VERSION 5.7 ;
  NOWIREEXTENSIONATPIN ON ;
  DIVIDERCHAR "/" ;
  BUSBITCHARS "[]" ;
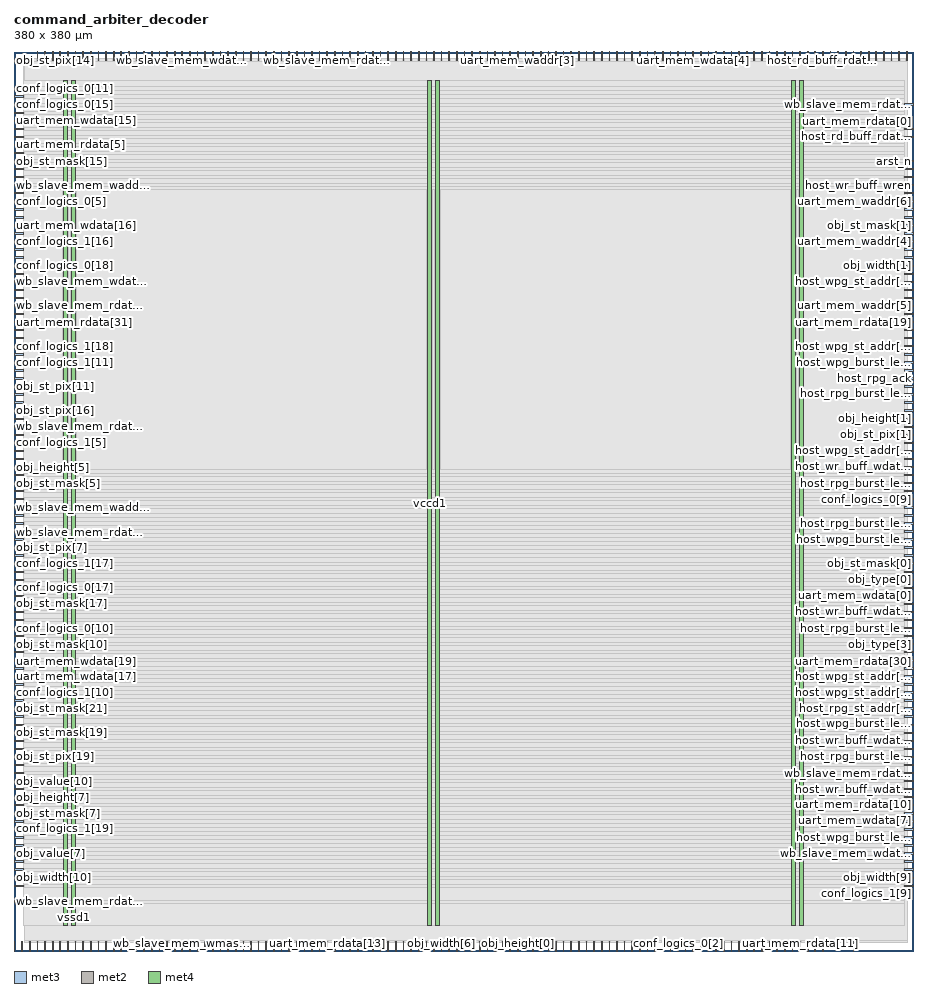
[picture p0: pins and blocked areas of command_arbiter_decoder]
MACRO command_arbiter_decoder
  CLASS BLOCK ;
  FOREIGN command_arbiter_decoder ;
  ORIGIN 0.000 0.000 ;
  SIZE 380.000 BY 380.000 ;
  PIN arst_n
    DIRECTION INPUT ;
    USE SIGNAL ;
    ANTENNAGATEAREA 1.286700 ;
    ANTENNADIFFAREA 0.434700 ;
    PORT
      LAYER met3 ;
        RECT 376.000 333.240 380.000 333.840 ;
    END
  END arst_n
  PIN clk
    DIRECTION INPUT ;
    USE SIGNAL ;
    ANTENNAGATEAREA 1.286700 ;
    ANTENNADIFFAREA 0.434700 ;
    PORT
      LAYER met3 ;
        RECT 0.000 27.240 4.000 27.840 ;
    END
  END clk
  PIN conf_logics_0[0]
    DIRECTION OUTPUT ;
    USE SIGNAL ;
    ANTENNADIFFAREA 0.340600 ;
    PORT
      LAYER met2 ;
        RECT 103.130 0.000 103.410 4.000 ;
    END
  END conf_logics_0[0]
  PIN conf_logics_0[10]
    DIRECTION OUTPUT ;
    USE SIGNAL ;
    ANTENNADIFFAREA 0.340600 ;
    PORT
      LAYER met3 ;
        RECT 0.000 136.040 4.000 136.640 ;
    END
  END conf_logics_0[10]
  PIN conf_logics_0[11]
    DIRECTION OUTPUT ;
    USE SIGNAL ;
    ANTENNADIFFAREA 0.340600 ;
    PORT
      LAYER met3 ;
        RECT 0.000 363.840 4.000 364.440 ;
    END
  END conf_logics_0[11]
  PIN conf_logics_0[12]
    DIRECTION OUTPUT ;
    USE SIGNAL ;
    ANTENNADIFFAREA 0.340600 ;
    PORT
      LAYER met2 ;
        RECT 9.750 376.000 10.030 380.000 ;
    END
  END conf_logics_0[12]
  PIN conf_logics_0[13]
    DIRECTION OUTPUT ;
    USE SIGNAL ;
    ANTENNADIFFAREA 0.340600 ;
    PORT
      LAYER met2 ;
        RECT 83.810 376.000 84.090 380.000 ;
    END
  END conf_logics_0[13]
  PIN conf_logics_0[14]
    DIRECTION OUTPUT ;
    USE SIGNAL ;
    ANTENNADIFFAREA 0.340600 ;
    PORT
      LAYER met2 ;
        RECT 164.310 376.000 164.590 380.000 ;
    END
  END conf_logics_0[14]
  PIN conf_logics_0[15]
    DIRECTION OUTPUT ;
    USE SIGNAL ;
    ANTENNADIFFAREA 0.340600 ;
    PORT
      LAYER met3 ;
        RECT 0.000 357.040 4.000 357.640 ;
    END
  END conf_logics_0[15]
  PIN conf_logics_0[16]
    DIRECTION OUTPUT ;
    USE SIGNAL ;
    ANTENNADIFFAREA 0.340600 ;
    PORT
      LAYER met3 ;
        RECT 0.000 309.440 4.000 310.040 ;
    END
  END conf_logics_0[16]
  PIN conf_logics_0[17]
    DIRECTION OUTPUT ;
    USE SIGNAL ;
    ANTENNADIFFAREA 0.340600 ;
    PORT
      LAYER met3 ;
        RECT 0.000 153.040 4.000 153.640 ;
    END
  END conf_logics_0[17]
  PIN conf_logics_0[18]
    DIRECTION OUTPUT ;
    USE SIGNAL ;
    ANTENNADIFFAREA 0.340600 ;
    PORT
      LAYER met3 ;
        RECT 0.000 289.040 4.000 289.640 ;
    END
  END conf_logics_0[18]
  PIN conf_logics_0[19]
    DIRECTION OUTPUT ;
    USE SIGNAL ;
    ANTENNADIFFAREA 0.340600 ;
    PORT
      LAYER met3 ;
        RECT 0.000 61.240 4.000 61.840 ;
    END
  END conf_logics_0[19]
  PIN conf_logics_0[1]
    DIRECTION OUTPUT ;
    USE SIGNAL ;
    ANTENNADIFFAREA 0.340600 ;
    PORT
      LAYER met2 ;
        RECT 186.850 376.000 187.130 380.000 ;
    END
  END conf_logics_0[1]
  PIN conf_logics_0[20]
    DIRECTION OUTPUT ;
    USE SIGNAL ;
    ANTENNADIFFAREA 0.340600 ;
    PORT
      LAYER met2 ;
        RECT 106.350 0.000 106.630 4.000 ;
    END
  END conf_logics_0[20]
  PIN conf_logics_0[2]
    DIRECTION OUTPUT ;
    USE SIGNAL ;
    ANTENNADIFFAREA 0.340600 ;
    PORT
      LAYER met2 ;
        RECT 280.230 0.000 280.510 4.000 ;
    END
  END conf_logics_0[2]
  PIN conf_logics_0[3]
    DIRECTION OUTPUT ;
    USE SIGNAL ;
    ANTENNADIFFAREA 0.340600 ;
    PORT
      LAYER met2 ;
        RECT 193.290 0.000 193.570 4.000 ;
    END
  END conf_logics_0[3]
  PIN conf_logics_0[4]
    DIRECTION OUTPUT ;
    USE SIGNAL ;
    ANTENNADIFFAREA 0.340600 ;
    PORT
      LAYER met2 ;
        RECT 199.730 376.000 200.010 380.000 ;
    END
  END conf_logics_0[4]
  PIN conf_logics_0[5]
    DIRECTION OUTPUT ;
    USE SIGNAL ;
    ANTENNADIFFAREA 0.340600 ;
    PORT
      LAYER met3 ;
        RECT 0.000 316.240 4.000 316.840 ;
    END
  END conf_logics_0[5]
  PIN conf_logics_0[6]
    DIRECTION OUTPUT ;
    USE SIGNAL ;
    ANTENNADIFFAREA 0.340600 ;
    PORT
      LAYER met2 ;
        RECT 170.750 0.000 171.030 4.000 ;
    END
  END conf_logics_0[6]
  PIN conf_logics_0[7]
    DIRECTION OUTPUT ;
    USE SIGNAL ;
    ANTENNADIFFAREA 0.340600 ;
    PORT
      LAYER met3 ;
        RECT 0.000 132.640 4.000 133.240 ;
    END
  END conf_logics_0[7]
  PIN conf_logics_0[8]
    DIRECTION OUTPUT ;
    USE SIGNAL ;
    ANTENNADIFFAREA 0.340600 ;
    PORT
      LAYER met2 ;
        RECT 116.010 0.000 116.290 4.000 ;
    END
  END conf_logics_0[8]
  PIN conf_logics_0[9]
    DIRECTION OUTPUT ;
    USE SIGNAL ;
    ANTENNADIFFAREA 0.340600 ;
    PORT
      LAYER met3 ;
        RECT 376.000 190.440 380.000 191.040 ;
    END
  END conf_logics_0[9]
  PIN conf_logics_1[0]
    DIRECTION OUTPUT ;
    USE SIGNAL ;
    ANTENNADIFFAREA 0.340600 ;
    PORT
      LAYER met2 ;
        RECT 177.190 0.000 177.470 4.000 ;
    END
  END conf_logics_1[0]
  PIN conf_logics_1[10]
    DIRECTION OUTPUT ;
    USE SIGNAL ;
    ANTENNADIFFAREA 0.340600 ;
    PORT
      LAYER met3 ;
        RECT 0.000 108.840 4.000 109.440 ;
    END
  END conf_logics_1[10]
  PIN conf_logics_1[11]
    DIRECTION OUTPUT ;
    USE SIGNAL ;
    ANTENNADIFFAREA 0.340600 ;
    PORT
      LAYER met3 ;
        RECT 0.000 248.240 4.000 248.840 ;
    END
  END conf_logics_1[11]
  PIN conf_logics_1[12]
    DIRECTION OUTPUT ;
    USE SIGNAL ;
    ANTENNADIFFAREA 0.340600 ;
    PORT
      LAYER met2 ;
        RECT 99.910 376.000 100.190 380.000 ;
    END
  END conf_logics_1[12]
  PIN conf_logics_1[13]
    DIRECTION OUTPUT ;
    USE SIGNAL ;
    ANTENNADIFFAREA 0.340600 ;
    PORT
      LAYER met3 ;
        RECT 0.000 258.440 4.000 259.040 ;
    END
  END conf_logics_1[13]
  PIN conf_logics_1[14]
    DIRECTION OUTPUT ;
    USE SIGNAL ;
    ANTENNADIFFAREA 0.340600 ;
    PORT
      LAYER met2 ;
        RECT 161.090 376.000 161.370 380.000 ;
    END
  END conf_logics_1[14]
  PIN conf_logics_1[15]
    DIRECTION OUTPUT ;
    USE SIGNAL ;
    ANTENNADIFFAREA 0.340600 ;
    PORT
      LAYER met3 ;
        RECT 0.000 329.840 4.000 330.440 ;
    END
  END conf_logics_1[15]
  PIN conf_logics_1[16]
    DIRECTION OUTPUT ;
    USE SIGNAL ;
    ANTENNADIFFAREA 0.340600 ;
    PORT
      LAYER met3 ;
        RECT 0.000 299.240 4.000 299.840 ;
    END
  END conf_logics_1[16]
  PIN conf_logics_1[17]
    DIRECTION OUTPUT ;
    USE SIGNAL ;
    ANTENNADIFFAREA 0.340600 ;
    PORT
      LAYER met3 ;
        RECT 0.000 163.240 4.000 163.840 ;
    END
  END conf_logics_1[17]
  PIN conf_logics_1[18]
    DIRECTION OUTPUT ;
    USE SIGNAL ;
    ANTENNADIFFAREA 0.340600 ;
    PORT
      LAYER met3 ;
        RECT 0.000 255.040 4.000 255.640 ;
    END
  END conf_logics_1[18]
  PIN conf_logics_1[19]
    DIRECTION OUTPUT ;
    USE SIGNAL ;
    ANTENNADIFFAREA 0.340600 ;
    PORT
      LAYER met3 ;
        RECT 0.000 54.440 4.000 55.040 ;
    END
  END conf_logics_1[19]
  PIN conf_logics_1[1]
    DIRECTION OUTPUT ;
    USE SIGNAL ;
    ANTENNADIFFAREA 0.340600 ;
    PORT
      LAYER met3 ;
        RECT 376.000 268.640 380.000 269.240 ;
    END
  END conf_logics_1[1]
  PIN conf_logics_1[20]
    DIRECTION OUTPUT ;
    USE SIGNAL ;
    ANTENNADIFFAREA 0.340600 ;
    PORT
      LAYER met3 ;
        RECT 0.000 47.640 4.000 48.240 ;
    END
  END conf_logics_1[20]
  PIN conf_logics_1[2]
    DIRECTION OUTPUT ;
    USE SIGNAL ;
    ANTENNADIFFAREA 0.340600 ;
    PORT
      LAYER met2 ;
        RECT 215.830 0.000 216.110 4.000 ;
    END
  END conf_logics_1[2]
  PIN conf_logics_1[3]
    DIRECTION OUTPUT ;
    USE SIGNAL ;
    ANTENNADIFFAREA 0.340600 ;
    PORT
      LAYER met2 ;
        RECT 199.730 0.000 200.010 4.000 ;
    END
  END conf_logics_1[3]
  PIN conf_logics_1[4]
    DIRECTION OUTPUT ;
    USE SIGNAL ;
    ANTENNADIFFAREA 0.340600 ;
    PORT
      LAYER met2 ;
        RECT 206.170 376.000 206.450 380.000 ;
    END
  END conf_logics_1[4]
  PIN conf_logics_1[5]
    DIRECTION OUTPUT ;
    USE SIGNAL ;
    ANTENNADIFFAREA 0.340600 ;
    PORT
      LAYER met3 ;
        RECT 0.000 214.240 4.000 214.840 ;
    END
  END conf_logics_1[5]
  PIN conf_logics_1[6]
    DIRECTION OUTPUT ;
    USE SIGNAL ;
    ANTENNADIFFAREA 0.340600 ;
    PORT
      LAYER met2 ;
        RECT 173.970 0.000 174.250 4.000 ;
    END
  END conf_logics_1[6]
  PIN conf_logics_1[7]
    DIRECTION OUTPUT ;
    USE SIGNAL ;
    ANTENNADIFFAREA 0.340600 ;
    PORT
      LAYER met3 ;
        RECT 0.000 166.640 4.000 167.240 ;
    END
  END conf_logics_1[7]
  PIN conf_logics_1[8]
    DIRECTION OUTPUT ;
    USE SIGNAL ;
    ANTENNADIFFAREA 0.340600 ;
    PORT
      LAYER met2 ;
        RECT 122.450 0.000 122.730 4.000 ;
    END
  END conf_logics_1[8]
  PIN conf_logics_1[9]
    DIRECTION OUTPUT ;
    USE SIGNAL ;
    ANTENNADIFFAREA 0.340600 ;
    PORT
      LAYER met3 ;
        RECT 376.000 27.240 380.000 27.840 ;
    END
  END conf_logics_1[9]
  PIN drw_inc_busy
    DIRECTION INPUT ;
    USE SIGNAL ;
    ANTENNAGATEAREA 0.631200 ;
    ANTENNADIFFAREA 0.434700 ;
    PORT
      LAYER met2 ;
        RECT 370.390 376.000 370.670 380.000 ;
    END
  END drw_inc_busy
  PIN drw_inc_start
    DIRECTION OUTPUT ;
    USE SIGNAL ;
    ANTENNADIFFAREA 0.340600 ;
    PORT
      LAYER met2 ;
        RECT 215.830 376.000 216.110 380.000 ;
    END
  END drw_inc_start
  PIN host_rd_buff_empty
    DIRECTION INPUT ;
    USE SIGNAL ;
    PORT
      LAYER met2 ;
        RECT 87.030 0.000 87.310 4.000 ;
    END
  END host_rd_buff_empty
  PIN host_rd_buff_rdata[0]
    DIRECTION INPUT ;
    USE SIGNAL ;
    ANTENNAGATEAREA 0.631200 ;
    ANTENNADIFFAREA 0.434700 ;
    PORT
      LAYER met3 ;
        RECT 376.000 343.440 380.000 344.040 ;
    END
  END host_rd_buff_rdata[0]
  PIN host_rd_buff_rdata[1]
    DIRECTION INPUT ;
    USE SIGNAL ;
    ANTENNAGATEAREA 0.631200 ;
    ANTENNADIFFAREA 0.434700 ;
    PORT
      LAYER met3 ;
        RECT 376.000 312.840 380.000 313.440 ;
    END
  END host_rd_buff_rdata[1]
  PIN host_rd_buff_rdata[2]
    DIRECTION INPUT ;
    USE SIGNAL ;
    ANTENNAGATEAREA 0.631200 ;
    ANTENNADIFFAREA 0.434700 ;
    PORT
      LAYER met2 ;
        RECT 90.250 376.000 90.530 380.000 ;
    END
  END host_rd_buff_rdata[2]
  PIN host_rd_buff_rdata[3]
    DIRECTION INPUT ;
    USE SIGNAL ;
    ANTENNAGATEAREA 0.631200 ;
    ANTENNADIFFAREA 0.434700 ;
    PORT
      LAYER met3 ;
        RECT 376.000 234.640 380.000 235.240 ;
    END
  END host_rd_buff_rdata[3]
  PIN host_rd_buff_rdata[4]
    DIRECTION INPUT ;
    USE SIGNAL ;
    ANTENNAGATEAREA 0.631200 ;
    ANTENNADIFFAREA 0.434700 ;
    PORT
      LAYER met2 ;
        RECT 341.410 376.000 341.690 380.000 ;
    END
  END host_rd_buff_rdata[4]
  PIN host_rd_buff_rdata[5]
    DIRECTION INPUT ;
    USE SIGNAL ;
    ANTENNAGATEAREA 0.631200 ;
    ANTENNADIFFAREA 0.434700 ;
    PORT
      LAYER met3 ;
        RECT 0.000 346.840 4.000 347.440 ;
    END
  END host_rd_buff_rdata[5]
  PIN host_rd_buff_rdata[6]
    DIRECTION INPUT ;
    USE SIGNAL ;
    ANTENNAGATEAREA 0.631200 ;
    ANTENNADIFFAREA 0.434700 ;
    PORT
      LAYER met2 ;
        RECT 305.990 376.000 306.270 380.000 ;
    END
  END host_rd_buff_rdata[6]
  PIN host_rd_buff_rdata[7]
    DIRECTION INPUT ;
    USE SIGNAL ;
    ANTENNAGATEAREA 0.631200 ;
    ANTENNADIFFAREA 0.434700 ;
    PORT
      LAYER met2 ;
        RECT 338.190 376.000 338.470 380.000 ;
    END
  END host_rd_buff_rdata[7]
  PIN host_rd_buff_rden
    DIRECTION OUTPUT ;
    USE SIGNAL ;
    ANTENNADIFFAREA 0.340600 ;
    PORT
      LAYER met3 ;
        RECT 376.000 37.440 380.000 38.040 ;
    END
  END host_rd_buff_rden
  PIN host_rpg_ack
    DIRECTION INPUT ;
    USE SIGNAL ;
    ANTENNAGATEAREA 0.631200 ;
    ANTENNADIFFAREA 0.434700 ;
    PORT
      LAYER met3 ;
        RECT 376.000 241.440 380.000 242.040 ;
    END
  END host_rpg_ack
  PIN host_rpg_burst_length[0]
    DIRECTION OUTPUT ;
    USE SIGNAL ;
    ANTENNADIFFAREA 0.340600 ;
    PORT
      LAYER met3 ;
        RECT 376.000 54.440 380.000 55.040 ;
    END
  END host_rpg_burst_length[0]
  PIN host_rpg_burst_length[1]
    DIRECTION OUTPUT ;
    USE SIGNAL ;
    ANTENNADIFFAREA 0.340600 ;
    PORT
      LAYER met3 ;
        RECT 376.000 319.640 380.000 320.240 ;
    END
  END host_rpg_burst_length[1]
  PIN host_rpg_burst_length[2]
    DIRECTION OUTPUT ;
    USE SIGNAL ;
    ANTENNADIFFAREA 0.340600 ;
    PORT
      LAYER met3 ;
        RECT 376.000 81.640 380.000 82.240 ;
    END
  END host_rpg_burst_length[2]
  PIN host_rpg_burst_length[3]
    DIRECTION OUTPUT ;
    USE SIGNAL ;
    ANTENNADIFFAREA 0.340600 ;
    PORT
      LAYER met3 ;
        RECT 376.000 132.640 380.000 133.240 ;
    END
  END host_rpg_burst_length[3]
  PIN host_rpg_burst_length[4]
    DIRECTION OUTPUT ;
    USE SIGNAL ;
    ANTENNADIFFAREA 0.340600 ;
    PORT
      LAYER met3 ;
        RECT 376.000 258.440 380.000 259.040 ;
    END
  END host_rpg_burst_length[4]
  PIN host_rpg_burst_length[5]
    DIRECTION OUTPUT ;
    USE SIGNAL ;
    ANTENNADIFFAREA 0.340600 ;
    PORT
      LAYER met3 ;
        RECT 376.000 238.040 380.000 238.640 ;
    END
  END host_rpg_burst_length[5]
  PIN host_rpg_burst_length[6]
    DIRECTION OUTPUT ;
    USE SIGNAL ;
    ANTENNADIFFAREA 0.340600 ;
    PORT
      LAYER met3 ;
        RECT 376.000 88.440 380.000 89.040 ;
    END
  END host_rpg_burst_length[6]
  PIN host_rpg_burst_length[7]
    DIRECTION OUTPUT ;
    USE SIGNAL ;
    ANTENNADIFFAREA 0.340600 ;
    PORT
      LAYER met3 ;
        RECT 376.000 180.240 380.000 180.840 ;
    END
  END host_rpg_burst_length[7]
  PIN host_rpg_burst_length[8]
    DIRECTION OUTPUT ;
    USE SIGNAL ;
    ANTENNADIFFAREA 0.340600 ;
    PORT
      LAYER met3 ;
        RECT 376.000 136.040 380.000 136.640 ;
    END
  END host_rpg_burst_length[8]
  PIN host_rpg_burst_length[9]
    DIRECTION OUTPUT ;
    USE SIGNAL ;
    ANTENNADIFFAREA 0.340600 ;
    PORT
      LAYER met3 ;
        RECT 376.000 193.840 380.000 194.440 ;
    END
  END host_rpg_burst_length[9]
  PIN host_rpg_busy
    DIRECTION OUTPUT ;
    USE SIGNAL ;
    ANTENNADIFFAREA 0.340600 ;
    PORT
      LAYER met3 ;
        RECT 376.000 278.840 380.000 279.440 ;
    END
  END host_rpg_busy
  PIN host_rpg_st_addr[0]
    DIRECTION OUTPUT ;
    USE SIGNAL ;
    ANTENNADIFFAREA 0.340600 ;
    PORT
      LAYER met3 ;
        RECT 376.000 78.240 380.000 78.840 ;
    END
  END host_rpg_st_addr[0]
  PIN host_rpg_st_addr[1]
    DIRECTION OUTPUT ;
    USE SIGNAL ;
    ANTENNADIFFAREA 0.340600 ;
    PORT
      LAYER met3 ;
        RECT 376.000 217.640 380.000 218.240 ;
    END
  END host_rpg_st_addr[1]
  PIN host_rpg_st_addr[2]
    DIRECTION OUTPUT ;
    USE SIGNAL ;
    ANTENNADIFFAREA 0.340600 ;
    PORT
      LAYER met3 ;
        RECT 376.000 95.240 380.000 95.840 ;
    END
  END host_rpg_st_addr[2]
  PIN host_rpg_st_addr[3]
    DIRECTION OUTPUT ;
    USE SIGNAL ;
    ANTENNADIFFAREA 0.340600 ;
    PORT
      LAYER met3 ;
        RECT 376.000 102.040 380.000 102.640 ;
    END
  END host_rpg_st_addr[3]
  PIN host_rpg_st_addr[4]
    DIRECTION OUTPUT ;
    USE SIGNAL ;
    ANTENNADIFFAREA 0.340600 ;
    PORT
      LAYER met3 ;
        RECT 376.000 295.840 380.000 296.440 ;
    END
  END host_rpg_st_addr[4]
  PIN host_rpg_st_addr[5]
    DIRECTION OUTPUT ;
    USE SIGNAL ;
    ANTENNADIFFAREA 0.340600 ;
    PORT
      LAYER met3 ;
        RECT 376.000 261.840 380.000 262.440 ;
    END
  END host_rpg_st_addr[5]
  PIN host_rpg_st_addr[6]
    DIRECTION OUTPUT ;
    USE SIGNAL ;
    ANTENNADIFFAREA 0.340600 ;
    PORT
      LAYER met2 ;
        RECT 277.010 0.000 277.290 4.000 ;
    END
  END host_rpg_st_addr[6]
  PIN host_rpg_st_addr[7]
    DIRECTION OUTPUT ;
    USE SIGNAL ;
    ANTENNADIFFAREA 0.340600 ;
    PORT
      LAYER met3 ;
        RECT 376.000 61.240 380.000 61.840 ;
    END
  END host_rpg_st_addr[7]
  PIN host_rpg_st_addr[8]
    DIRECTION OUTPUT ;
    USE SIGNAL ;
    ANTENNADIFFAREA 0.340600 ;
    PORT
      LAYER met2 ;
        RECT 257.690 0.000 257.970 4.000 ;
    END
  END host_rpg_st_addr[8]
  PIN host_rpg_st_addr[9]
    DIRECTION OUTPUT ;
    USE SIGNAL ;
    ANTENNADIFFAREA 0.340600 ;
    PORT
      LAYER met3 ;
        RECT 376.000 166.640 380.000 167.240 ;
    END
  END host_rpg_st_addr[9]
  PIN host_wpg_ack
    DIRECTION INPUT ;
    USE SIGNAL ;
    ANTENNAGATEAREA 0.631200 ;
    ANTENNADIFFAREA 0.434700 ;
    PORT
      LAYER met2 ;
        RECT 222.270 376.000 222.550 380.000 ;
    END
  END host_wpg_ack
  PIN host_wpg_burst_length[0]
    DIRECTION OUTPUT ;
    USE SIGNAL ;
    ANTENNADIFFAREA 0.340600 ;
    PORT
      LAYER met3 ;
        RECT 376.000 47.640 380.000 48.240 ;
    END
  END host_wpg_burst_length[0]
  PIN host_wpg_burst_length[1]
    DIRECTION OUTPUT ;
    USE SIGNAL ;
    ANTENNADIFFAREA 0.340600 ;
    PORT
      LAYER met3 ;
        RECT 376.000 302.640 380.000 303.240 ;
    END
  END host_wpg_burst_length[1]
  PIN host_wpg_burst_length[2]
    DIRECTION OUTPUT ;
    USE SIGNAL ;
    ANTENNADIFFAREA 0.340600 ;
    PORT
      LAYER met3 ;
        RECT 376.000 98.640 380.000 99.240 ;
    END
  END host_wpg_burst_length[2]
  PIN host_wpg_burst_length[3]
    DIRECTION OUTPUT ;
    USE SIGNAL ;
    ANTENNADIFFAREA 0.340600 ;
    PORT
      LAYER met3 ;
        RECT 376.000 105.440 380.000 106.040 ;
    END
  END host_wpg_burst_length[3]
  PIN host_wpg_burst_length[4]
    DIRECTION OUTPUT ;
    USE SIGNAL ;
    ANTENNADIFFAREA 0.340600 ;
    PORT
      LAYER met3 ;
        RECT 376.000 248.240 380.000 248.840 ;
    END
  END host_wpg_burst_length[4]
  PIN host_wpg_burst_length[5]
    DIRECTION OUTPUT ;
    USE SIGNAL ;
    ANTENNADIFFAREA 0.340600 ;
    PORT
      LAYER met3 ;
        RECT 376.000 200.640 380.000 201.240 ;
    END
  END host_wpg_burst_length[5]
  PIN host_wpg_burst_length[6]
    DIRECTION OUTPUT ;
    USE SIGNAL ;
    ANTENNADIFFAREA 0.340600 ;
    PORT
      LAYER met3 ;
        RECT 376.000 122.440 380.000 123.040 ;
    END
  END host_wpg_burst_length[6]
  PIN host_wpg_burst_length[7]
    DIRECTION OUTPUT ;
    USE SIGNAL ;
    ANTENNADIFFAREA 0.340600 ;
    PORT
      LAYER met3 ;
        RECT 376.000 173.440 380.000 174.040 ;
    END
  END host_wpg_burst_length[7]
  PIN host_wpg_burst_length[8]
    DIRECTION OUTPUT ;
    USE SIGNAL ;
    ANTENNADIFFAREA 0.340600 ;
    PORT
      LAYER met2 ;
        RECT 264.130 0.000 264.410 4.000 ;
    END
  END host_wpg_burst_length[8]
  PIN host_wpg_burst_length[9]
    DIRECTION OUTPUT ;
    USE SIGNAL ;
    ANTENNADIFFAREA 0.340600 ;
    PORT
      LAYER met3 ;
        RECT 376.000 187.040 380.000 187.640 ;
    END
  END host_wpg_burst_length[9]
  PIN host_wpg_busy
    DIRECTION OUTPUT ;
    USE SIGNAL ;
    ANTENNADIFFAREA 0.340600 ;
    PORT
      LAYER met2 ;
        RECT 225.490 376.000 225.770 380.000 ;
    END
  END host_wpg_busy
  PIN host_wpg_st_addr[0]
    DIRECTION OUTPUT ;
    USE SIGNAL ;
    ANTENNADIFFAREA 0.340600 ;
    PORT
      LAYER met3 ;
        RECT 376.000 71.440 380.000 72.040 ;
    END
  END host_wpg_st_addr[0]
  PIN host_wpg_st_addr[1]
    DIRECTION OUTPUT ;
    USE SIGNAL ;
    ANTENNADIFFAREA 0.340600 ;
    PORT
      LAYER met3 ;
        RECT 376.000 282.240 380.000 282.840 ;
    END
  END host_wpg_st_addr[1]
  PIN host_wpg_st_addr[2]
    DIRECTION OUTPUT ;
    USE SIGNAL ;
    ANTENNADIFFAREA 0.340600 ;
    PORT
      LAYER met3 ;
        RECT 376.000 108.840 380.000 109.440 ;
    END
  END host_wpg_st_addr[2]
  PIN host_wpg_st_addr[3]
    DIRECTION OUTPUT ;
    USE SIGNAL ;
    ANTENNADIFFAREA 0.340600 ;
    PORT
      LAYER met3 ;
        RECT 376.000 112.240 380.000 112.840 ;
    END
  END host_wpg_st_addr[3]
  PIN host_wpg_st_addr[4]
    DIRECTION OUTPUT ;
    USE SIGNAL ;
    ANTENNADIFFAREA 0.340600 ;
    PORT
      LAYER met3 ;
        RECT 376.000 255.040 380.000 255.640 ;
    END
  END host_wpg_st_addr[4]
  PIN host_wpg_st_addr[5]
    DIRECTION OUTPUT ;
    USE SIGNAL ;
    ANTENNADIFFAREA 0.340600 ;
    PORT
      LAYER met3 ;
        RECT 376.000 210.840 380.000 211.440 ;
    END
  END host_wpg_st_addr[5]
  PIN host_wpg_st_addr[6]
    DIRECTION OUTPUT ;
    USE SIGNAL ;
    ANTENNADIFFAREA 0.340600 ;
    PORT
      LAYER met3 ;
        RECT 376.000 115.640 380.000 116.240 ;
    END
  END host_wpg_st_addr[6]
  PIN host_wpg_st_addr[7]
    DIRECTION OUTPUT ;
    USE SIGNAL ;
    ANTENNADIFFAREA 0.340600 ;
    PORT
      LAYER met3 ;
        RECT 376.000 34.040 380.000 34.640 ;
    END
  END host_wpg_st_addr[7]
  PIN host_wpg_st_addr[8]
    DIRECTION OUTPUT ;
    USE SIGNAL ;
    ANTENNADIFFAREA 0.340600 ;
    PORT
      LAYER met2 ;
        RECT 254.470 0.000 254.750 4.000 ;
    END
  END host_wpg_st_addr[8]
  PIN host_wpg_st_addr[9]
    DIRECTION OUTPUT ;
    USE SIGNAL ;
    ANTENNADIFFAREA 0.340600 ;
    PORT
      LAYER met3 ;
        RECT 376.000 329.840 380.000 330.440 ;
    END
  END host_wpg_st_addr[9]
  PIN host_wr_buff_full
    DIRECTION INPUT ;
    USE SIGNAL ;
    ANTENNAGATEAREA 0.631200 ;
    ANTENNADIFFAREA 0.434700 ;
    PORT
      LAYER met3 ;
        RECT 376.000 275.440 380.000 276.040 ;
    END
  END host_wr_buff_full
  PIN host_wr_buff_wdata[0]
    DIRECTION OUTPUT ;
    USE SIGNAL ;
    ANTENNADIFFAREA 0.340600 ;
    PORT
      LAYER met3 ;
        RECT 376.000 149.640 380.000 150.240 ;
    END
  END host_wr_buff_wdata[0]
  PIN host_wr_buff_wdata[1]
    DIRECTION OUTPUT ;
    USE SIGNAL ;
    ANTENNADIFFAREA 0.340600 ;
    PORT
      LAYER met3 ;
        RECT 376.000 207.440 380.000 208.040 ;
    END
  END host_wr_buff_wdata[1]
  PIN host_wr_buff_wdata[2]
    DIRECTION OUTPUT ;
    USE SIGNAL ;
    ANTENNADIFFAREA 0.340600 ;
    PORT
      LAYER met3 ;
        RECT 376.000 142.840 380.000 143.440 ;
    END
  END host_wr_buff_wdata[2]
  PIN host_wr_buff_wdata[3]
    DIRECTION OUTPUT ;
    USE SIGNAL ;
    ANTENNADIFFAREA 0.340600 ;
    PORT
      LAYER met3 ;
        RECT 376.000 91.840 380.000 92.440 ;
    END
  END host_wr_buff_wdata[3]
  PIN host_wr_buff_wdata[4]
    DIRECTION OUTPUT ;
    USE SIGNAL ;
    ANTENNADIFFAREA 0.340600 ;
    PORT
      LAYER met3 ;
        RECT 376.000 244.840 380.000 245.440 ;
    END
  END host_wr_buff_wdata[4]
  PIN host_wr_buff_wdata[5]
    DIRECTION OUTPUT ;
    USE SIGNAL ;
    ANTENNADIFFAREA 0.340600 ;
    PORT
      LAYER met3 ;
        RECT 376.000 197.240 380.000 197.840 ;
    END
  END host_wr_buff_wdata[5]
  PIN host_wr_buff_wdata[6]
    DIRECTION OUTPUT ;
    USE SIGNAL ;
    ANTENNADIFFAREA 0.340600 ;
    PORT
      LAYER met3 ;
        RECT 376.000 85.040 380.000 85.640 ;
    END
  END host_wr_buff_wdata[6]
  PIN host_wr_buff_wdata[7]
    DIRECTION OUTPUT ;
    USE SIGNAL ;
    ANTENNADIFFAREA 0.340600 ;
    PORT
      LAYER met3 ;
        RECT 376.000 68.040 380.000 68.640 ;
    END
  END host_wr_buff_wdata[7]
  PIN host_wr_buff_wren
    DIRECTION OUTPUT ;
    USE SIGNAL ;
    ANTENNADIFFAREA 0.340600 ;
    PORT
      LAYER met3 ;
        RECT 376.000 323.040 380.000 323.640 ;
    END
  END host_wr_buff_wren
  PIN obj_height[0]
    DIRECTION OUTPUT ;
    USE SIGNAL ;
    ANTENNADIFFAREA 0.340600 ;
    PORT
      LAYER met2 ;
        RECT 212.610 0.000 212.890 4.000 ;
    END
  END obj_height[0]
  PIN obj_height[10]
    DIRECTION OUTPUT ;
    USE SIGNAL ;
    ANTENNADIFFAREA 0.340600 ;
    PORT
      LAYER met3 ;
        RECT 0.000 51.040 4.000 51.640 ;
    END
  END obj_height[10]
  PIN obj_height[1]
    DIRECTION OUTPUT ;
    USE SIGNAL ;
    ANTENNADIFFAREA 0.340600 ;
    PORT
      LAYER met3 ;
        RECT 376.000 224.440 380.000 225.040 ;
    END
  END obj_height[1]
  PIN obj_height[2]
    DIRECTION OUTPUT ;
    USE SIGNAL ;
    ANTENNADIFFAREA 0.340600 ;
    PORT
      LAYER met2 ;
        RECT 225.490 0.000 225.770 4.000 ;
    END
  END obj_height[2]
  PIN obj_height[3]
    DIRECTION OUTPUT ;
    USE SIGNAL ;
    ANTENNADIFFAREA 0.340600 ;
    PORT
      LAYER met2 ;
        RECT 248.030 0.000 248.310 4.000 ;
    END
  END obj_height[3]
  PIN obj_height[4]
    DIRECTION OUTPUT ;
    USE SIGNAL ;
    ANTENNADIFFAREA 0.340600 ;
    PORT
      LAYER met2 ;
        RECT 190.070 376.000 190.350 380.000 ;
    END
  END obj_height[4]
  PIN obj_height[5]
    DIRECTION OUTPUT ;
    USE SIGNAL ;
    ANTENNADIFFAREA 0.340600 ;
    PORT
      LAYER met3 ;
        RECT 0.000 204.040 4.000 204.640 ;
    END
  END obj_height[5]
  PIN obj_height[6]
    DIRECTION OUTPUT ;
    USE SIGNAL ;
    ANTENNADIFFAREA 0.340600 ;
    PORT
      LAYER met2 ;
        RECT 119.230 0.000 119.510 4.000 ;
    END
  END obj_height[6]
  PIN obj_height[7]
    DIRECTION OUTPUT ;
    USE SIGNAL ;
    ANTENNADIFFAREA 0.340600 ;
    PORT
      LAYER met3 ;
        RECT 0.000 64.640 4.000 65.240 ;
    END
  END obj_height[7]
  PIN obj_height[8]
    DIRECTION OUTPUT ;
    USE SIGNAL ;
    ANTENNADIFFAREA 0.340600 ;
    PORT
      LAYER met2 ;
        RECT 141.770 0.000 142.050 4.000 ;
    END
  END obj_height[8]
  PIN obj_height[9]
    DIRECTION OUTPUT ;
    USE SIGNAL ;
    ANTENNADIFFAREA 0.340600 ;
    PORT
      LAYER met3 ;
        RECT 376.000 176.840 380.000 177.440 ;
    END
  END obj_height[9]
  PIN obj_st_mask[0]
    DIRECTION OUTPUT ;
    USE SIGNAL ;
    ANTENNADIFFAREA 0.340600 ;
    PORT
      LAYER met3 ;
        RECT 376.000 163.240 380.000 163.840 ;
    END
  END obj_st_mask[0]
  PIN obj_st_mask[10]
    DIRECTION OUTPUT ;
    USE SIGNAL ;
    ANTENNADIFFAREA 0.340600 ;
    PORT
      LAYER met3 ;
        RECT 0.000 129.240 4.000 129.840 ;
    END
  END obj_st_mask[10]
  PIN obj_st_mask[11]
    DIRECTION OUTPUT ;
    USE SIGNAL ;
    ANTENNADIFFAREA 0.340600 ;
    PORT
      LAYER met3 ;
        RECT 0.000 234.640 4.000 235.240 ;
    END
  END obj_st_mask[11]
  PIN obj_st_mask[12]
    DIRECTION OUTPUT ;
    USE SIGNAL ;
    ANTENNADIFFAREA 0.340600 ;
    PORT
      LAYER met2 ;
        RECT 128.890 376.000 129.170 380.000 ;
    END
  END obj_st_mask[12]
  PIN obj_st_mask[13]
    DIRECTION OUTPUT ;
    USE SIGNAL ;
    ANTENNADIFFAREA 0.340600 ;
    PORT
      LAYER met2 ;
        RECT 74.150 376.000 74.430 380.000 ;
    END
  END obj_st_mask[13]
  PIN obj_st_mask[14]
    DIRECTION OUTPUT ;
    USE SIGNAL ;
    ANTENNADIFFAREA 0.340600 ;
    PORT
      LAYER met2 ;
        RECT 180.410 376.000 180.690 380.000 ;
    END
  END obj_st_mask[14]
  PIN obj_st_mask[15]
    DIRECTION OUTPUT ;
    USE SIGNAL ;
    ANTENNADIFFAREA 0.340600 ;
    PORT
      LAYER met3 ;
        RECT 0.000 333.240 4.000 333.840 ;
    END
  END obj_st_mask[15]
  PIN obj_st_mask[16]
    DIRECTION OUTPUT ;
    USE SIGNAL ;
    ANTENNADIFFAREA 0.340600 ;
    PORT
      LAYER met3 ;
        RECT 0.000 295.840 4.000 296.440 ;
    END
  END obj_st_mask[16]
  PIN obj_st_mask[17]
    DIRECTION OUTPUT ;
    USE SIGNAL ;
    ANTENNADIFFAREA 0.340600 ;
    PORT
      LAYER met3 ;
        RECT 0.000 146.240 4.000 146.840 ;
    END
  END obj_st_mask[17]
  PIN obj_st_mask[18]
    DIRECTION OUTPUT ;
    USE SIGNAL ;
    ANTENNADIFFAREA 0.340600 ;
    PORT
      LAYER met3 ;
        RECT 0.000 285.640 4.000 286.240 ;
    END
  END obj_st_mask[18]
  PIN obj_st_mask[19]
    DIRECTION OUTPUT ;
    USE SIGNAL ;
    ANTENNADIFFAREA 0.340600 ;
    PORT
      LAYER met3 ;
        RECT 0.000 91.840 4.000 92.440 ;
    END
  END obj_st_mask[19]
  PIN obj_st_mask[1]
    DIRECTION OUTPUT ;
    USE SIGNAL ;
    ANTENNADIFFAREA 0.340600 ;
    PORT
      LAYER met3 ;
        RECT 376.000 306.040 380.000 306.640 ;
    END
  END obj_st_mask[1]
  PIN obj_st_mask[20]
    DIRECTION OUTPUT ;
    USE SIGNAL ;
    ANTENNADIFFAREA 0.340600 ;
    PORT
      LAYER met2 ;
        RECT 109.570 0.000 109.850 4.000 ;
    END
  END obj_st_mask[20]
  PIN obj_st_mask[21]
    DIRECTION OUTPUT ;
    USE SIGNAL ;
    ANTENNADIFFAREA 0.340600 ;
    PORT
      LAYER met3 ;
        RECT 0.000 102.040 4.000 102.640 ;
    END
  END obj_st_mask[21]
  PIN obj_st_mask[2]
    DIRECTION OUTPUT ;
    USE SIGNAL ;
    ANTENNADIFFAREA 0.340600 ;
    PORT
      LAYER met2 ;
        RECT 251.250 0.000 251.530 4.000 ;
    END
  END obj_st_mask[2]
  PIN obj_st_mask[3]
    DIRECTION OUTPUT ;
    USE SIGNAL ;
    ANTENNADIFFAREA 0.340600 ;
    PORT
      LAYER met2 ;
        RECT 244.810 0.000 245.090 4.000 ;
    END
  END obj_st_mask[3]
  PIN obj_st_mask[4]
    DIRECTION OUTPUT ;
    USE SIGNAL ;
    ANTENNADIFFAREA 0.340600 ;
    PORT
      LAYER met2 ;
        RECT 196.510 376.000 196.790 380.000 ;
    END
  END obj_st_mask[4]
  PIN obj_st_mask[5]
    DIRECTION OUTPUT ;
    USE SIGNAL ;
    ANTENNADIFFAREA 0.340600 ;
    PORT
      LAYER met3 ;
        RECT 0.000 197.240 4.000 197.840 ;
    END
  END obj_st_mask[5]
  PIN obj_st_mask[6]
    DIRECTION OUTPUT ;
    USE SIGNAL ;
    ANTENNADIFFAREA 0.340600 ;
    PORT
      LAYER met2 ;
        RECT 164.310 0.000 164.590 4.000 ;
    END
  END obj_st_mask[6]
  PIN obj_st_mask[7]
    DIRECTION OUTPUT ;
    USE SIGNAL ;
    ANTENNADIFFAREA 0.340600 ;
    PORT
      LAYER met3 ;
        RECT 0.000 57.840 4.000 58.440 ;
    END
  END obj_st_mask[7]
  PIN obj_st_mask[8]
    DIRECTION OUTPUT ;
    USE SIGNAL ;
    ANTENNADIFFAREA 0.340600 ;
    PORT
      LAYER met2 ;
        RECT 144.990 0.000 145.270 4.000 ;
    END
  END obj_st_mask[8]
  PIN obj_st_mask[9]
    DIRECTION OUTPUT ;
    USE SIGNAL ;
    ANTENNADIFFAREA 0.340600 ;
    PORT
      LAYER met3 ;
        RECT 376.000 183.640 380.000 184.240 ;
    END
  END obj_st_mask[9]
  PIN obj_st_pix[0]
    DIRECTION OUTPUT ;
    USE SIGNAL ;
    ANTENNADIFFAREA 0.340600 ;
    PORT
      LAYER met2 ;
        RECT 209.390 0.000 209.670 4.000 ;
    END
  END obj_st_pix[0]
  PIN obj_st_pix[10]
    DIRECTION OUTPUT ;
    USE SIGNAL ;
    ANTENNADIFFAREA 0.340600 ;
    PORT
      LAYER met3 ;
        RECT 0.000 122.440 4.000 123.040 ;
    END
  END obj_st_pix[10]
  PIN obj_st_pix[11]
    DIRECTION OUTPUT ;
    USE SIGNAL ;
    ANTENNADIFFAREA 0.340600 ;
    PORT
      LAYER met3 ;
        RECT 0.000 238.040 4.000 238.640 ;
    END
  END obj_st_pix[11]
  PIN obj_st_pix[12]
    DIRECTION OUTPUT ;
    USE SIGNAL ;
    ANTENNADIFFAREA 0.340600 ;
    PORT
      LAYER met2 ;
        RECT 12.970 376.000 13.250 380.000 ;
    END
  END obj_st_pix[12]
  PIN obj_st_pix[13]
    DIRECTION OUTPUT ;
    USE SIGNAL ;
    ANTENNADIFFAREA 0.340600 ;
    PORT
      LAYER met3 ;
        RECT 0.000 261.840 4.000 262.440 ;
    END
  END obj_st_pix[13]
  PIN obj_st_pix[14]
    DIRECTION OUTPUT ;
    USE SIGNAL ;
    ANTENNADIFFAREA 0.340600 ;
    PORT
      LAYER met2 ;
        RECT 16.190 376.000 16.470 380.000 ;
    END
  END obj_st_pix[14]
  PIN obj_st_pix[15]
    DIRECTION OUTPUT ;
    USE SIGNAL ;
    ANTENNADIFFAREA 0.340600 ;
    PORT
      LAYER met3 ;
        RECT 0.000 200.640 4.000 201.240 ;
    END
  END obj_st_pix[15]
  PIN obj_st_pix[16]
    DIRECTION OUTPUT ;
    USE SIGNAL ;
    ANTENNADIFFAREA 0.340600 ;
    PORT
      LAYER met3 ;
        RECT 0.000 227.840 4.000 228.440 ;
    END
  END obj_st_pix[16]
  PIN obj_st_pix[17]
    DIRECTION OUTPUT ;
    USE SIGNAL ;
    ANTENNADIFFAREA 0.340600 ;
    PORT
      LAYER met3 ;
        RECT 0.000 159.840 4.000 160.440 ;
    END
  END obj_st_pix[17]
  PIN obj_st_pix[18]
    DIRECTION OUTPUT ;
    USE SIGNAL ;
    ANTENNADIFFAREA 0.340600 ;
    PORT
      LAYER met3 ;
        RECT 0.000 251.640 4.000 252.240 ;
    END
  END obj_st_pix[18]
  PIN obj_st_pix[19]
    DIRECTION OUTPUT ;
    USE SIGNAL ;
    ANTENNADIFFAREA 0.340600 ;
    PORT
      LAYER met3 ;
        RECT 0.000 81.640 4.000 82.240 ;
    END
  END obj_st_pix[19]
  PIN obj_st_pix[1]
    DIRECTION OUTPUT ;
    USE SIGNAL ;
    ANTENNADIFFAREA 0.340600 ;
    PORT
      LAYER met3 ;
        RECT 376.000 221.040 380.000 221.640 ;
    END
  END obj_st_pix[1]
  PIN obj_st_pix[20]
    DIRECTION OUTPUT ;
    USE SIGNAL ;
    ANTENNADIFFAREA 0.340600 ;
    PORT
      LAYER met3 ;
        RECT 0.000 88.440 4.000 89.040 ;
    END
  END obj_st_pix[20]
  PIN obj_st_pix[21]
    DIRECTION OUTPUT ;
    USE SIGNAL ;
    ANTENNADIFFAREA 0.340600 ;
    PORT
      LAYER met3 ;
        RECT 0.000 112.240 4.000 112.840 ;
    END
  END obj_st_pix[21]
  PIN obj_st_pix[2]
    DIRECTION OUTPUT ;
    USE SIGNAL ;
    ANTENNADIFFAREA 0.340600 ;
    PORT
      LAYER met2 ;
        RECT 219.050 0.000 219.330 4.000 ;
    END
  END obj_st_pix[2]
  PIN obj_st_pix[3]
    DIRECTION OUTPUT ;
    USE SIGNAL ;
    ANTENNADIFFAREA 0.340600 ;
    PORT
      LAYER met2 ;
        RECT 222.270 0.000 222.550 4.000 ;
    END
  END obj_st_pix[3]
  PIN obj_st_pix[4]
    DIRECTION OUTPUT ;
    USE SIGNAL ;
    ANTENNADIFFAREA 0.340600 ;
    PORT
      LAYER met2 ;
        RECT 209.390 376.000 209.670 380.000 ;
    END
  END obj_st_pix[4]
  PIN obj_st_pix[5]
    DIRECTION OUTPUT ;
    USE SIGNAL ;
    ANTENNADIFFAREA 0.340600 ;
    PORT
      LAYER met3 ;
        RECT 0.000 360.440 4.000 361.040 ;
    END
  END obj_st_pix[5]
  PIN obj_st_pix[6]
    DIRECTION OUTPUT ;
    USE SIGNAL ;
    ANTENNADIFFAREA 0.340600 ;
    PORT
      LAYER met2 ;
        RECT 157.870 0.000 158.150 4.000 ;
    END
  END obj_st_pix[6]
  PIN obj_st_pix[7]
    DIRECTION OUTPUT ;
    USE SIGNAL ;
    ANTENNADIFFAREA 0.340600 ;
    PORT
      LAYER met3 ;
        RECT 0.000 170.040 4.000 170.640 ;
    END
  END obj_st_pix[7]
  PIN obj_st_pix[8]
    DIRECTION OUTPUT ;
    USE SIGNAL ;
    ANTENNADIFFAREA 0.340600 ;
    PORT
      LAYER met2 ;
        RECT 135.330 0.000 135.610 4.000 ;
    END
  END obj_st_pix[8]
  PIN obj_st_pix[9]
    DIRECTION OUTPUT ;
    USE SIGNAL ;
    ANTENNADIFFAREA 0.340600 ;
    PORT
      LAYER met2 ;
        RECT 190.070 0.000 190.350 4.000 ;
    END
  END obj_st_pix[9]
  PIN obj_type[0]
    DIRECTION OUTPUT ;
    USE SIGNAL ;
    ANTENNADIFFAREA 0.340600 ;
    PORT
      LAYER met3 ;
        RECT 376.000 156.440 380.000 157.040 ;
    END
  END obj_type[0]
  PIN obj_type[1]
    DIRECTION OUTPUT ;
    USE SIGNAL ;
    ANTENNADIFFAREA 0.340600 ;
    PORT
      LAYER met3 ;
        RECT 376.000 204.040 380.000 204.640 ;
    END
  END obj_type[1]
  PIN obj_type[2]
    DIRECTION OUTPUT ;
    USE SIGNAL ;
    ANTENNADIFFAREA 0.340600 ;
    PORT
      LAYER met3 ;
        RECT 376.000 139.440 380.000 140.040 ;
    END
  END obj_type[2]
  PIN obj_type[3]
    DIRECTION OUTPUT ;
    USE SIGNAL ;
    ANTENNADIFFAREA 0.340600 ;
    PORT
      LAYER met3 ;
        RECT 376.000 129.240 380.000 129.840 ;
    END
  END obj_type[3]
  PIN obj_value[0]
    DIRECTION OUTPUT ;
    USE SIGNAL ;
    ANTENNADIFFAREA 0.340600 ;
    PORT
      LAYER met2 ;
        RECT 186.850 0.000 187.130 4.000 ;
    END
  END obj_value[0]
  PIN obj_value[10]
    DIRECTION OUTPUT ;
    USE SIGNAL ;
    ANTENNADIFFAREA 0.340600 ;
    PORT
      LAYER met3 ;
        RECT 0.000 68.040 4.000 68.640 ;
    END
  END obj_value[10]
  PIN obj_value[11]
    DIRECTION OUTPUT ;
    USE SIGNAL ;
    ANTENNADIFFAREA 0.340600 ;
    PORT
      LAYER met2 ;
        RECT 87.030 376.000 87.310 380.000 ;
    END
  END obj_value[11]
  PIN obj_value[12]
    DIRECTION OUTPUT ;
    USE SIGNAL ;
    ANTENNADIFFAREA 0.340600 ;
    PORT
      LAYER met2 ;
        RECT 54.830 376.000 55.110 380.000 ;
    END
  END obj_value[12]
  PIN obj_value[13]
    DIRECTION OUTPUT ;
    USE SIGNAL ;
    ANTENNADIFFAREA 0.340600 ;
    PORT
      LAYER met2 ;
        RECT 109.570 376.000 109.850 380.000 ;
    END
  END obj_value[13]
  PIN obj_value[14]
    DIRECTION OUTPUT ;
    USE SIGNAL ;
    ANTENNADIFFAREA 0.340600 ;
    PORT
      LAYER met2 ;
        RECT 183.630 376.000 183.910 380.000 ;
    END
  END obj_value[14]
  PIN obj_value[1]
    DIRECTION OUTPUT ;
    USE SIGNAL ;
    ANTENNADIFFAREA 0.340600 ;
    PORT
      LAYER met2 ;
        RECT 170.750 376.000 171.030 380.000 ;
    END
  END obj_value[1]
  PIN obj_value[2]
    DIRECTION OUTPUT ;
    USE SIGNAL ;
    ANTENNADIFFAREA 0.340600 ;
    PORT
      LAYER met2 ;
        RECT 202.950 0.000 203.230 4.000 ;
    END
  END obj_value[2]
  PIN obj_value[3]
    DIRECTION OUTPUT ;
    USE SIGNAL ;
    ANTENNADIFFAREA 0.340600 ;
    PORT
      LAYER met2 ;
        RECT 183.630 0.000 183.910 4.000 ;
    END
  END obj_value[3]
  PIN obj_value[4]
    DIRECTION OUTPUT ;
    USE SIGNAL ;
    ANTENNADIFFAREA 0.340600 ;
    PORT
      LAYER met2 ;
        RECT 148.210 376.000 148.490 380.000 ;
    END
  END obj_value[4]
  PIN obj_value[5]
    DIRECTION OUTPUT ;
    USE SIGNAL ;
    ANTENNADIFFAREA 0.340600 ;
    PORT
      LAYER met2 ;
        RECT 112.790 376.000 113.070 380.000 ;
    END
  END obj_value[5]
  PIN obj_value[6]
    DIRECTION OUTPUT ;
    USE SIGNAL ;
    ANTENNADIFFAREA 0.340600 ;
    PORT
      LAYER met2 ;
        RECT 167.530 0.000 167.810 4.000 ;
    END
  END obj_value[6]
  PIN obj_value[7]
    DIRECTION OUTPUT ;
    USE SIGNAL ;
    ANTENNADIFFAREA 0.340600 ;
    PORT
      LAYER met3 ;
        RECT 0.000 40.840 4.000 41.440 ;
    END
  END obj_value[7]
  PIN obj_value[8]
    DIRECTION OUTPUT ;
    USE SIGNAL ;
    ANTENNADIFFAREA 0.340600 ;
    PORT
      LAYER met2 ;
        RECT 138.550 0.000 138.830 4.000 ;
    END
  END obj_value[8]
  PIN obj_value[9]
    DIRECTION OUTPUT ;
    USE SIGNAL ;
    ANTENNADIFFAREA 0.340600 ;
    PORT
      LAYER met2 ;
        RECT 196.510 0.000 196.790 4.000 ;
    END
  END obj_value[9]
  PIN obj_width[0]
    DIRECTION OUTPUT ;
    USE SIGNAL ;
    ANTENNADIFFAREA 0.340600 ;
    PORT
      LAYER met3 ;
        RECT 376.000 159.840 380.000 160.440 ;
    END
  END obj_width[0]
  PIN obj_width[10]
    DIRECTION OUTPUT ;
    USE SIGNAL ;
    ANTENNADIFFAREA 0.340600 ;
    PORT
      LAYER met3 ;
        RECT 0.000 30.640 4.000 31.240 ;
    END
  END obj_width[10]
  PIN obj_width[1]
    DIRECTION OUTPUT ;
    USE SIGNAL ;
    ANTENNADIFFAREA 0.340600 ;
    PORT
      LAYER met3 ;
        RECT 376.000 289.040 380.000 289.640 ;
    END
  END obj_width[1]
  PIN obj_width[2]
    DIRECTION OUTPUT ;
    USE SIGNAL ;
    ANTENNADIFFAREA 0.340600 ;
    PORT
      LAYER met2 ;
        RECT 228.710 0.000 228.990 4.000 ;
    END
  END obj_width[2]
  PIN obj_width[3]
    DIRECTION OUTPUT ;
    USE SIGNAL ;
    ANTENNADIFFAREA 0.340600 ;
    PORT
      LAYER met2 ;
        RECT 238.370 0.000 238.650 4.000 ;
    END
  END obj_width[3]
  PIN obj_width[4]
    DIRECTION OUTPUT ;
    USE SIGNAL ;
    ANTENNADIFFAREA 0.340600 ;
    PORT
      LAYER met2 ;
        RECT 202.950 376.000 203.230 380.000 ;
    END
  END obj_width[4]
  PIN obj_width[5]
    DIRECTION OUTPUT ;
    USE SIGNAL ;
    ANTENNADIFFAREA 0.340600 ;
    PORT
      LAYER met3 ;
        RECT 0.000 217.640 4.000 218.240 ;
    END
  END obj_width[5]
  PIN obj_width[6]
    DIRECTION OUTPUT ;
    USE SIGNAL ;
    ANTENNADIFFAREA 0.340600 ;
    PORT
      LAYER met2 ;
        RECT 180.410 0.000 180.690 4.000 ;
    END
  END obj_width[6]
  PIN obj_width[7]
    DIRECTION OUTPUT ;
    USE SIGNAL ;
    ANTENNADIFFAREA 0.340600 ;
    PORT
      LAYER met3 ;
        RECT 0.000 105.440 4.000 106.040 ;
    END
  END obj_width[7]
  PIN obj_width[8]
    DIRECTION OUTPUT ;
    USE SIGNAL ;
    ANTENNADIFFAREA 0.340600 ;
    PORT
      LAYER met2 ;
        RECT 151.430 0.000 151.710 4.000 ;
    END
  END obj_width[8]
  PIN obj_width[9]
    DIRECTION OUTPUT ;
    USE SIGNAL ;
    ANTENNADIFFAREA 0.340600 ;
    PORT
      LAYER met3 ;
        RECT 376.000 30.640 380.000 31.240 ;
    END
  END obj_width[9]
  PIN uart_mem_raddr[0]
    DIRECTION INPUT ;
    USE SIGNAL ;
    PORT
      LAYER met2 ;
        RECT 64.490 0.000 64.770 4.000 ;
    END
  END uart_mem_raddr[0]
  PIN uart_mem_raddr[1]
    DIRECTION INPUT ;
    USE SIGNAL ;
    PORT
      LAYER met2 ;
        RECT 25.850 0.000 26.130 4.000 ;
    END
  END uart_mem_raddr[1]
  PIN uart_mem_raddr[2]
    DIRECTION INPUT ;
    USE SIGNAL ;
    PORT
      LAYER met2 ;
        RECT 58.050 0.000 58.330 4.000 ;
    END
  END uart_mem_raddr[2]
  PIN uart_mem_raddr[3]
    DIRECTION INPUT ;
    USE SIGNAL ;
    PORT
      LAYER met2 ;
        RECT 61.270 0.000 61.550 4.000 ;
    END
  END uart_mem_raddr[3]
  PIN uart_mem_raddr[4]
    DIRECTION INPUT ;
    USE SIGNAL ;
    PORT
      LAYER met2 ;
        RECT 54.830 0.000 55.110 4.000 ;
    END
  END uart_mem_raddr[4]
  PIN uart_mem_raddr[5]
    DIRECTION INPUT ;
    USE SIGNAL ;
    PORT
      LAYER met2 ;
        RECT 45.170 0.000 45.450 4.000 ;
    END
  END uart_mem_raddr[5]
  PIN uart_mem_raddr[6]
    DIRECTION INPUT ;
    USE SIGNAL ;
    PORT
      LAYER met2 ;
        RECT 315.650 0.000 315.930 4.000 ;
    END
  END uart_mem_raddr[6]
  PIN uart_mem_raddr[7]
    DIRECTION INPUT ;
    USE SIGNAL ;
    PORT
      LAYER met2 ;
        RECT 6.530 0.000 6.810 4.000 ;
    END
  END uart_mem_raddr[7]
  PIN uart_mem_rdata[0]
    DIRECTION OUTPUT ;
    USE SIGNAL ;
    ANTENNADIFFAREA 0.340600 ;
    PORT
      LAYER met3 ;
        RECT 376.000 346.840 380.000 347.440 ;
    END
  END uart_mem_rdata[0]
  PIN uart_mem_rdata[10]
    DIRECTION OUTPUT ;
    USE SIGNAL ;
    PORT
      LAYER met3 ;
        RECT 376.000 64.640 380.000 65.240 ;
    END
  END uart_mem_rdata[10]
  PIN uart_mem_rdata[11]
    DIRECTION OUTPUT ;
    USE SIGNAL ;
    PORT
      LAYER met2 ;
        RECT 331.750 0.000 332.030 4.000 ;
    END
  END uart_mem_rdata[11]
  PIN uart_mem_rdata[12]
    DIRECTION OUTPUT ;
    USE SIGNAL ;
    PORT
      LAYER met3 ;
        RECT 0.000 85.040 4.000 85.640 ;
    END
  END uart_mem_rdata[12]
  PIN uart_mem_rdata[13]
    DIRECTION OUTPUT ;
    USE SIGNAL ;
    PORT
      LAYER met2 ;
        RECT 132.110 0.000 132.390 4.000 ;
    END
  END uart_mem_rdata[13]
  PIN uart_mem_rdata[14]
    DIRECTION OUTPUT ;
    USE SIGNAL ;
    PORT
      LAYER met2 ;
        RECT 206.170 0.000 206.450 4.000 ;
    END
  END uart_mem_rdata[14]
  PIN uart_mem_rdata[15]
    DIRECTION OUTPUT ;
    USE SIGNAL ;
    PORT
      LAYER met3 ;
        RECT 0.000 336.640 4.000 337.240 ;
    END
  END uart_mem_rdata[15]
  PIN uart_mem_rdata[16]
    DIRECTION OUTPUT ;
    USE SIGNAL ;
    PORT
      LAYER met2 ;
        RECT 270.570 0.000 270.850 4.000 ;
    END
  END uart_mem_rdata[16]
  PIN uart_mem_rdata[17]
    DIRECTION OUTPUT ;
    USE SIGNAL ;
    PORT
      LAYER met3 ;
        RECT 0.000 268.640 4.000 269.240 ;
    END
  END uart_mem_rdata[17]
  PIN uart_mem_rdata[18]
    DIRECTION OUTPUT ;
    USE SIGNAL ;
    PORT
      LAYER met3 ;
        RECT 376.000 44.240 380.000 44.840 ;
    END
  END uart_mem_rdata[18]
  PIN uart_mem_rdata[19]
    DIRECTION OUTPUT ;
    USE SIGNAL ;
    PORT
      LAYER met3 ;
        RECT 376.000 265.240 380.000 265.840 ;
    END
  END uart_mem_rdata[19]
  PIN uart_mem_rdata[1]
    DIRECTION OUTPUT ;
    USE SIGNAL ;
    ANTENNADIFFAREA 0.340600 ;
    PORT
      LAYER met3 ;
        RECT 376.000 285.640 380.000 286.240 ;
    END
  END uart_mem_rdata[1]
  PIN uart_mem_rdata[20]
    DIRECTION OUTPUT ;
    USE SIGNAL ;
    PORT
      LAYER met2 ;
        RECT 41.950 0.000 42.230 4.000 ;
    END
  END uart_mem_rdata[20]
  PIN uart_mem_rdata[21]
    DIRECTION OUTPUT ;
    USE SIGNAL ;
    PORT
      LAYER met3 ;
        RECT 0.000 302.640 4.000 303.240 ;
    END
  END uart_mem_rdata[21]
  PIN uart_mem_rdata[22]
    DIRECTION OUTPUT ;
    USE SIGNAL ;
    PORT
      LAYER met2 ;
        RECT 273.790 0.000 274.070 4.000 ;
    END
  END uart_mem_rdata[22]
  PIN uart_mem_rdata[23]
    DIRECTION OUTPUT ;
    USE SIGNAL ;
    PORT
      LAYER met2 ;
        RECT 148.210 0.000 148.490 4.000 ;
    END
  END uart_mem_rdata[23]
  PIN uart_mem_rdata[24]
    DIRECTION OUTPUT ;
    USE SIGNAL ;
    PORT
      LAYER met3 ;
        RECT 0.000 95.240 4.000 95.840 ;
    END
  END uart_mem_rdata[24]
  PIN uart_mem_rdata[25]
    DIRECTION OUTPUT ;
    USE SIGNAL ;
    PORT
      LAYER met2 ;
        RECT 167.530 376.000 167.810 380.000 ;
    END
  END uart_mem_rdata[25]
  PIN uart_mem_rdata[26]
    DIRECTION OUTPUT ;
    USE SIGNAL ;
    PORT
      LAYER met2 ;
        RECT 318.870 0.000 319.150 4.000 ;
    END
  END uart_mem_rdata[26]
  PIN uart_mem_rdata[27]
    DIRECTION OUTPUT ;
    USE SIGNAL ;
    PORT
      LAYER met2 ;
        RECT 45.170 376.000 45.450 380.000 ;
    END
  END uart_mem_rdata[27]
  PIN uart_mem_rdata[28]
    DIRECTION OUTPUT ;
    USE SIGNAL ;
    PORT
      LAYER met2 ;
        RECT 315.650 376.000 315.930 380.000 ;
    END
  END uart_mem_rdata[28]
  PIN uart_mem_rdata[29]
    DIRECTION OUTPUT ;
    USE SIGNAL ;
    PORT
      LAYER met2 ;
        RECT 29.070 0.000 29.350 4.000 ;
    END
  END uart_mem_rdata[29]
  PIN uart_mem_rdata[2]
    DIRECTION OUTPUT ;
    USE SIGNAL ;
    ANTENNADIFFAREA 0.340600 ;
    PORT
      LAYER met2 ;
        RECT 64.490 376.000 64.770 380.000 ;
    END
  END uart_mem_rdata[2]
  PIN uart_mem_rdata[30]
    DIRECTION OUTPUT ;
    USE SIGNAL ;
    PORT
      LAYER met3 ;
        RECT 376.000 119.040 380.000 119.640 ;
    END
  END uart_mem_rdata[30]
  PIN uart_mem_rdata[31]
    DIRECTION OUTPUT ;
    USE SIGNAL ;
    PORT
      LAYER met3 ;
        RECT 0.000 265.240 4.000 265.840 ;
    END
  END uart_mem_rdata[31]
  PIN uart_mem_rdata[3]
    DIRECTION OUTPUT ;
    USE SIGNAL ;
    ANTENNADIFFAREA 0.340600 ;
    PORT
      LAYER met3 ;
        RECT 376.000 292.440 380.000 293.040 ;
    END
  END uart_mem_rdata[3]
  PIN uart_mem_rdata[4]
    DIRECTION OUTPUT ;
    USE SIGNAL ;
    ANTENNADIFFAREA 0.340600 ;
    PORT
      LAYER met2 ;
        RECT 244.810 376.000 245.090 380.000 ;
    END
  END uart_mem_rdata[4]
  PIN uart_mem_rdata[5]
    DIRECTION OUTPUT ;
    USE SIGNAL ;
    ANTENNADIFFAREA 0.340600 ;
    PORT
      LAYER met3 ;
        RECT 0.000 340.040 4.000 340.640 ;
    END
  END uart_mem_rdata[5]
  PIN uart_mem_rdata[6]
    DIRECTION OUTPUT ;
    USE SIGNAL ;
    ANTENNADIFFAREA 0.340600 ;
    PORT
      LAYER met2 ;
        RECT 254.470 376.000 254.750 380.000 ;
    END
  END uart_mem_rdata[6]
  PIN uart_mem_rdata[7]
    DIRECTION OUTPUT ;
    USE SIGNAL ;
    ANTENNADIFFAREA 0.340600 ;
    PORT
      LAYER met2 ;
        RECT 334.970 376.000 335.250 380.000 ;
    END
  END uart_mem_rdata[7]
  PIN uart_mem_rdata[8]
    DIRECTION OUTPUT ;
    USE SIGNAL ;
    PORT
      LAYER met2 ;
        RECT 193.290 376.000 193.570 380.000 ;
    END
  END uart_mem_rdata[8]
  PIN uart_mem_rdata[9]
    DIRECTION OUTPUT ;
    USE SIGNAL ;
    PORT
      LAYER met3 ;
        RECT 376.000 125.840 380.000 126.440 ;
    END
  END uart_mem_rdata[9]
  PIN uart_mem_rdy
    DIRECTION OUTPUT ;
    USE SIGNAL ;
    PORT
      LAYER met3 ;
        RECT 376.000 309.440 380.000 310.040 ;
    END
  END uart_mem_rdy
  PIN uart_mem_re
    DIRECTION INPUT ;
    USE SIGNAL ;
    ANTENNAGATEAREA 0.631200 ;
    ANTENNADIFFAREA 0.434700 ;
    PORT
      LAYER met3 ;
        RECT 376.000 51.040 380.000 51.640 ;
    END
  END uart_mem_re
  PIN uart_mem_waddr[0]
    DIRECTION INPUT ;
    USE SIGNAL ;
    ANTENNAGATEAREA 0.593700 ;
    ANTENNADIFFAREA 0.434700 ;
    PORT
      LAYER met2 ;
        RECT 219.050 376.000 219.330 380.000 ;
    END
  END uart_mem_waddr[0]
  PIN uart_mem_waddr[1]
    DIRECTION INPUT ;
    USE SIGNAL ;
    ANTENNAGATEAREA 0.593700 ;
    ANTENNADIFFAREA 0.434700 ;
    PORT
      LAYER met2 ;
        RECT 125.670 376.000 125.950 380.000 ;
    END
  END uart_mem_waddr[1]
  PIN uart_mem_waddr[2]
    DIRECTION INPUT ;
    USE SIGNAL ;
    ANTENNAGATEAREA 0.593700 ;
    ANTENNADIFFAREA 0.434700 ;
    PORT
      LAYER met2 ;
        RECT 119.230 376.000 119.510 380.000 ;
    END
  END uart_mem_waddr[2]
  PIN uart_mem_waddr[3]
    DIRECTION INPUT ;
    USE SIGNAL ;
    ANTENNAGATEAREA 0.647700 ;
    ANTENNADIFFAREA 0.434700 ;
    PORT
      LAYER met2 ;
        RECT 212.610 376.000 212.890 380.000 ;
    END
  END uart_mem_waddr[3]
  PIN uart_mem_waddr[4]
    DIRECTION INPUT ;
    USE SIGNAL ;
    ANTENNAGATEAREA 0.631200 ;
    ANTENNADIFFAREA 0.434700 ;
    PORT
      LAYER met3 ;
        RECT 376.000 299.240 380.000 299.840 ;
    END
  END uart_mem_waddr[4]
  PIN uart_mem_waddr[5]
    DIRECTION INPUT ;
    USE SIGNAL ;
    ANTENNAGATEAREA 0.647700 ;
    ANTENNADIFFAREA 0.434700 ;
    PORT
      LAYER met3 ;
        RECT 376.000 272.040 380.000 272.640 ;
    END
  END uart_mem_waddr[5]
  PIN uart_mem_waddr[6]
    DIRECTION INPUT ;
    USE SIGNAL ;
    ANTENNAGATEAREA 0.560700 ;
    ANTENNADIFFAREA 0.434700 ;
    PORT
      LAYER met3 ;
        RECT 376.000 316.240 380.000 316.840 ;
    END
  END uart_mem_waddr[6]
  PIN uart_mem_waddr[7]
    DIRECTION INPUT ;
    USE SIGNAL ;
    ANTENNAGATEAREA 0.647700 ;
    ANTENNADIFFAREA 0.434700 ;
    PORT
      LAYER met3 ;
        RECT 376.000 251.640 380.000 252.240 ;
    END
  END uart_mem_waddr[7]
  PIN uart_mem_wdata[0]
    DIRECTION INPUT ;
    USE SIGNAL ;
    ANTENNAGATEAREA 0.682200 ;
    ANTENNADIFFAREA 0.434700 ;
    PORT
      LAYER met3 ;
        RECT 376.000 153.040 380.000 153.640 ;
    END
  END uart_mem_wdata[0]
  PIN uart_mem_wdata[10]
    DIRECTION INPUT ;
    USE SIGNAL ;
    ANTENNAGATEAREA 0.647700 ;
    ANTENNADIFFAREA 0.434700 ;
    PORT
      LAYER met3 ;
        RECT 0.000 139.440 4.000 140.040 ;
    END
  END uart_mem_wdata[10]
  PIN uart_mem_wdata[11]
    DIRECTION INPUT ;
    USE SIGNAL ;
    ANTENNAGATEAREA 0.647700 ;
    ANTENNADIFFAREA 0.434700 ;
    PORT
      LAYER met3 ;
        RECT 0.000 244.840 4.000 245.440 ;
    END
  END uart_mem_wdata[11]
  PIN uart_mem_wdata[12]
    DIRECTION INPUT ;
    USE SIGNAL ;
    ANTENNAGATEAREA 0.560700 ;
    ANTENNADIFFAREA 0.434700 ;
    PORT
      LAYER met2 ;
        RECT 32.290 376.000 32.570 380.000 ;
    END
  END uart_mem_wdata[12]
  PIN uart_mem_wdata[13]
    DIRECTION INPUT ;
    USE SIGNAL ;
    ANTENNAGATEAREA 0.647700 ;
    ANTENNADIFFAREA 0.434700 ;
    PORT
      LAYER met2 ;
        RECT 25.850 376.000 26.130 380.000 ;
    END
  END uart_mem_wdata[13]
  PIN uart_mem_wdata[14]
    DIRECTION INPUT ;
    USE SIGNAL ;
    ANTENNAGATEAREA 0.631200 ;
    ANTENNADIFFAREA 0.434700 ;
    PORT
      LAYER met2 ;
        RECT 122.450 376.000 122.730 380.000 ;
    END
  END uart_mem_wdata[14]
  PIN uart_mem_wdata[15]
    DIRECTION INPUT ;
    USE SIGNAL ;
    ANTENNAGATEAREA 0.631200 ;
    ANTENNADIFFAREA 0.434700 ;
    PORT
      LAYER met3 ;
        RECT 0.000 350.240 4.000 350.840 ;
    END
  END uart_mem_wdata[15]
  PIN uart_mem_wdata[16]
    DIRECTION INPUT ;
    USE SIGNAL ;
    ANTENNAGATEAREA 0.631200 ;
    ANTENNADIFFAREA 0.434700 ;
    PORT
      LAYER met3 ;
        RECT 0.000 306.040 4.000 306.640 ;
    END
  END uart_mem_wdata[16]
  PIN uart_mem_wdata[17]
    DIRECTION INPUT ;
    USE SIGNAL ;
    ANTENNAGATEAREA 0.631200 ;
    ANTENNADIFFAREA 0.434700 ;
    PORT
      LAYER met3 ;
        RECT 0.000 115.640 4.000 116.240 ;
    END
  END uart_mem_wdata[17]
  PIN uart_mem_wdata[18]
    DIRECTION INPUT ;
    USE SIGNAL ;
    ANTENNAGATEAREA 0.631200 ;
    ANTENNADIFFAREA 0.434700 ;
    PORT
      LAYER met3 ;
        RECT 0.000 278.840 4.000 279.440 ;
    END
  END uart_mem_wdata[18]
  PIN uart_mem_wdata[19]
    DIRECTION INPUT ;
    USE SIGNAL ;
    ANTENNAGATEAREA 0.631200 ;
    ANTENNADIFFAREA 0.434700 ;
    PORT
      LAYER met3 ;
        RECT 0.000 119.040 4.000 119.640 ;
    END
  END uart_mem_wdata[19]
  PIN uart_mem_wdata[1]
    DIRECTION INPUT ;
    USE SIGNAL ;
    ANTENNAGATEAREA 0.860700 ;
    ANTENNADIFFAREA 0.434700 ;
    PORT
      LAYER met3 ;
        RECT 376.000 231.240 380.000 231.840 ;
    END
  END uart_mem_wdata[1]
  PIN uart_mem_wdata[20]
    DIRECTION INPUT ;
    USE SIGNAL ;
    ANTENNAGATEAREA 0.647700 ;
    ANTENNADIFFAREA 0.434700 ;
    PORT
      LAYER met2 ;
        RECT 112.790 0.000 113.070 4.000 ;
    END
  END uart_mem_wdata[20]
  PIN uart_mem_wdata[21]
    DIRECTION INPUT ;
    USE SIGNAL ;
    ANTENNAGATEAREA 0.631200 ;
    ANTENNADIFFAREA 0.434700 ;
    PORT
      LAYER met3 ;
        RECT 0.000 74.840 4.000 75.440 ;
    END
  END uart_mem_wdata[21]
  PIN uart_mem_wdata[22]
    DIRECTION INPUT ;
    USE SIGNAL ;
    PORT
      LAYER met2 ;
        RECT 48.390 0.000 48.670 4.000 ;
    END
  END uart_mem_wdata[22]
  PIN uart_mem_wdata[23]
    DIRECTION INPUT ;
    USE SIGNAL ;
    PORT
      LAYER met2 ;
        RECT 0.090 0.000 0.370 4.000 ;
    END
  END uart_mem_wdata[23]
  PIN uart_mem_wdata[24]
    DIRECTION INPUT ;
    USE SIGNAL ;
    PORT
      LAYER met2 ;
        RECT 38.730 0.000 39.010 4.000 ;
    END
  END uart_mem_wdata[24]
  PIN uart_mem_wdata[25]
    DIRECTION INPUT ;
    USE SIGNAL ;
    PORT
      LAYER met2 ;
        RECT 341.410 0.000 341.690 4.000 ;
    END
  END uart_mem_wdata[25]
  PIN uart_mem_wdata[26]
    DIRECTION INPUT ;
    USE SIGNAL ;
    PORT
      LAYER met2 ;
        RECT 322.090 0.000 322.370 4.000 ;
    END
  END uart_mem_wdata[26]
  PIN uart_mem_wdata[27]
    DIRECTION INPUT ;
    USE SIGNAL ;
    PORT
      LAYER met2 ;
        RECT 9.750 0.000 10.030 4.000 ;
    END
  END uart_mem_wdata[27]
  PIN uart_mem_wdata[28]
    DIRECTION INPUT ;
    USE SIGNAL ;
    PORT
      LAYER met2 ;
        RECT 16.190 0.000 16.470 4.000 ;
    END
  END uart_mem_wdata[28]
  PIN uart_mem_wdata[29]
    DIRECTION INPUT ;
    USE SIGNAL ;
    PORT
      LAYER met2 ;
        RECT 338.190 0.000 338.470 4.000 ;
    END
  END uart_mem_wdata[29]
  PIN uart_mem_wdata[2]
    DIRECTION INPUT ;
    USE SIGNAL ;
    ANTENNAGATEAREA 0.682200 ;
    ANTENNADIFFAREA 0.434700 ;
    PORT
      LAYER met2 ;
        RECT 283.450 0.000 283.730 4.000 ;
    END
  END uart_mem_wdata[2]
  PIN uart_mem_wdata[30]
    DIRECTION INPUT ;
    USE SIGNAL ;
    PORT
      LAYER met2 ;
        RECT 309.210 0.000 309.490 4.000 ;
    END
  END uart_mem_wdata[30]
  PIN uart_mem_wdata[31]
    DIRECTION INPUT ;
    USE SIGNAL ;
    PORT
      LAYER met2 ;
        RECT 32.290 0.000 32.570 4.000 ;
    END
  END uart_mem_wdata[31]
  PIN uart_mem_wdata[3]
    DIRECTION INPUT ;
    USE SIGNAL ;
    ANTENNAGATEAREA 0.682200 ;
    ANTENNADIFFAREA 0.434700 ;
    PORT
      LAYER met2 ;
        RECT 286.670 0.000 286.950 4.000 ;
    END
  END uart_mem_wdata[3]
  PIN uart_mem_wdata[4]
    DIRECTION INPUT ;
    USE SIGNAL ;
    ANTENNAGATEAREA 0.682200 ;
    ANTENNADIFFAREA 0.434700 ;
    PORT
      LAYER met2 ;
        RECT 286.670 376.000 286.950 380.000 ;
    END
  END uart_mem_wdata[4]
  PIN uart_mem_wdata[5]
    DIRECTION INPUT ;
    USE SIGNAL ;
    ANTENNAGATEAREA 0.860700 ;
    ANTENNADIFFAREA 0.434700 ;
    PORT
      LAYER met3 ;
        RECT 376.000 227.840 380.000 228.440 ;
    END
  END uart_mem_wdata[5]
  PIN uart_mem_wdata[6]
    DIRECTION INPUT ;
    USE SIGNAL ;
    ANTENNAGATEAREA 0.682200 ;
    ANTENNADIFFAREA 0.434700 ;
    PORT
      LAYER met2 ;
        RECT 267.350 0.000 267.630 4.000 ;
    END
  END uart_mem_wdata[6]
  PIN uart_mem_wdata[7]
    DIRECTION INPUT ;
    USE SIGNAL ;
    ANTENNAGATEAREA 0.860700 ;
    ANTENNADIFFAREA 0.434700 ;
    PORT
      LAYER met3 ;
        RECT 376.000 57.840 380.000 58.440 ;
    END
  END uart_mem_wdata[7]
  PIN uart_mem_wdata[8]
    DIRECTION INPUT ;
    USE SIGNAL ;
    ANTENNAGATEAREA 0.682200 ;
    ANTENNADIFFAREA 0.434700 ;
    PORT
      LAYER met2 ;
        RECT 260.910 0.000 261.190 4.000 ;
    END
  END uart_mem_wdata[8]
  PIN uart_mem_wdata[9]
    DIRECTION INPUT ;
    USE SIGNAL ;
    ANTENNAGATEAREA 0.860700 ;
    ANTENNADIFFAREA 0.434700 ;
    PORT
      LAYER met3 ;
        RECT 376.000 170.040 380.000 170.640 ;
    END
  END uart_mem_wdata[9]
  PIN uart_mem_we
    DIRECTION INPUT ;
    USE SIGNAL ;
    ANTENNAGATEAREA 0.860700 ;
    ANTENNADIFFAREA 0.434700 ;
    PORT
      LAYER met2 ;
        RECT 116.010 376.000 116.290 380.000 ;
    END
  END uart_mem_we
  PIN up_soft_reset
    DIRECTION OUTPUT ;
    USE SIGNAL ;
    ANTENNADIFFAREA 0.340600 ;
    PORT
      LAYER met2 ;
        RECT 231.930 376.000 232.210 380.000 ;
    END
  END up_soft_reset
  PIN up_soft_reset_req
    DIRECTION OUTPUT ;
    USE SIGNAL ;
    ANTENNADIFFAREA 0.340600 ;
    PORT
      LAYER met2 ;
        RECT 312.430 376.000 312.710 380.000 ;
    END
  END up_soft_reset_req
  PIN vccd1
    DIRECTION INOUT ;
    USE POWER ;
    PORT
      LAYER met4 ;
        RECT 21.040 10.640 22.640 367.440 ;
    END
    PORT
      LAYER met4 ;
        RECT 174.640 10.640 176.240 367.440 ;
    END
    PORT
      LAYER met4 ;
        RECT 328.240 10.640 329.840 367.440 ;
    END
  END vccd1
  PIN vssd1
    DIRECTION INOUT ;
    USE GROUND ;
    PORT
      LAYER met4 ;
        RECT 24.340 10.640 25.940 367.440 ;
    END
    PORT
      LAYER met4 ;
        RECT 177.940 10.640 179.540 367.440 ;
    END
    PORT
      LAYER met4 ;
        RECT 331.540 10.640 333.140 367.440 ;
    END
  END vssd1
  PIN wb_mem_sys_wb_ack_o
    DIRECTION INPUT ;
    USE SIGNAL ;
    ANTENNAGATEAREA 0.631200 ;
    ANTENNADIFFAREA 0.434700 ;
    PORT
      LAYER met2 ;
        RECT 267.350 376.000 267.630 380.000 ;
    END
  END wb_mem_sys_wb_ack_o
  PIN wb_slave_mem_raddr[0]
    DIRECTION INPUT ;
    USE SIGNAL ;
    ANTENNAGATEAREA 0.631200 ;
    ANTENNADIFFAREA 0.434700 ;
    PORT
      LAYER met2 ;
        RECT 270.570 376.000 270.850 380.000 ;
    END
  END wb_slave_mem_raddr[0]
  PIN wb_slave_mem_raddr[10]
    DIRECTION INPUT ;
    USE SIGNAL ;
    ANTENNAGATEAREA 0.631200 ;
    ANTENNADIFFAREA 0.434700 ;
    PORT
      LAYER met2 ;
        RECT 251.250 376.000 251.530 380.000 ;
    END
  END wb_slave_mem_raddr[10]
  PIN wb_slave_mem_raddr[11]
    DIRECTION INPUT ;
    USE SIGNAL ;
    ANTENNAGATEAREA 0.631200 ;
    ANTENNADIFFAREA 0.434700 ;
    PORT
      LAYER met2 ;
        RECT 273.790 376.000 274.070 380.000 ;
    END
  END wb_slave_mem_raddr[11]
  PIN wb_slave_mem_raddr[12]
    DIRECTION INPUT ;
    USE SIGNAL ;
    ANTENNAGATEAREA 0.631200 ;
    ANTENNADIFFAREA 0.434700 ;
    PORT
      LAYER met2 ;
        RECT 299.550 376.000 299.830 380.000 ;
    END
  END wb_slave_mem_raddr[12]
  PIN wb_slave_mem_raddr[13]
    DIRECTION INPUT ;
    USE SIGNAL ;
    ANTENNAGATEAREA 0.631200 ;
    ANTENNADIFFAREA 0.434700 ;
    PORT
      LAYER met2 ;
        RECT 277.010 376.000 277.290 380.000 ;
    END
  END wb_slave_mem_raddr[13]
  PIN wb_slave_mem_raddr[14]
    DIRECTION INPUT ;
    USE SIGNAL ;
    ANTENNAGATEAREA 0.631200 ;
    ANTENNADIFFAREA 0.434700 ;
    PORT
      LAYER met2 ;
        RECT 354.290 376.000 354.570 380.000 ;
    END
  END wb_slave_mem_raddr[14]
  PIN wb_slave_mem_raddr[15]
    DIRECTION INPUT ;
    USE SIGNAL ;
    ANTENNAGATEAREA 0.631200 ;
    ANTENNADIFFAREA 0.434700 ;
    PORT
      LAYER met2 ;
        RECT 351.070 376.000 351.350 380.000 ;
    END
  END wb_slave_mem_raddr[15]
  PIN wb_slave_mem_raddr[16]
    DIRECTION INPUT ;
    USE SIGNAL ;
    ANTENNAGATEAREA 0.631200 ;
    ANTENNADIFFAREA 0.434700 ;
    PORT
      LAYER met2 ;
        RECT 235.150 376.000 235.430 380.000 ;
    END
  END wb_slave_mem_raddr[16]
  PIN wb_slave_mem_raddr[17]
    DIRECTION INPUT ;
    USE SIGNAL ;
    ANTENNAGATEAREA 0.631200 ;
    ANTENNADIFFAREA 0.434700 ;
    PORT
      LAYER met2 ;
        RECT 344.630 376.000 344.910 380.000 ;
    END
  END wb_slave_mem_raddr[17]
  PIN wb_slave_mem_raddr[18]
    DIRECTION INPUT ;
    USE SIGNAL ;
    ANTENNAGATEAREA 0.631200 ;
    ANTENNADIFFAREA 0.434700 ;
    PORT
      LAYER met2 ;
        RECT 363.950 376.000 364.230 380.000 ;
    END
  END wb_slave_mem_raddr[18]
  PIN wb_slave_mem_raddr[19]
    DIRECTION INPUT ;
    USE SIGNAL ;
    ANTENNAGATEAREA 0.631200 ;
    ANTENNADIFFAREA 0.434700 ;
    PORT
      LAYER met2 ;
        RECT 241.590 376.000 241.870 380.000 ;
    END
  END wb_slave_mem_raddr[19]
  PIN wb_slave_mem_raddr[1]
    DIRECTION INPUT ;
    USE SIGNAL ;
    ANTENNAGATEAREA 0.631200 ;
    ANTENNADIFFAREA 0.434700 ;
    PORT
      LAYER met2 ;
        RECT 280.230 376.000 280.510 380.000 ;
    END
  END wb_slave_mem_raddr[1]
  PIN wb_slave_mem_raddr[20]
    DIRECTION INPUT ;
    USE SIGNAL ;
    ANTENNAGATEAREA 0.631200 ;
    ANTENNADIFFAREA 0.434700 ;
    PORT
      LAYER met2 ;
        RECT 376.830 376.000 377.110 380.000 ;
    END
  END wb_slave_mem_raddr[20]
  PIN wb_slave_mem_raddr[21]
    DIRECTION INPUT ;
    USE SIGNAL ;
    ANTENNAGATEAREA 0.631200 ;
    ANTENNADIFFAREA 0.434700 ;
    PORT
      LAYER met2 ;
        RECT 360.730 376.000 361.010 380.000 ;
    END
  END wb_slave_mem_raddr[21]
  PIN wb_slave_mem_raddr[22]
    DIRECTION INPUT ;
    USE SIGNAL ;
    ANTENNAGATEAREA 0.631200 ;
    ANTENNADIFFAREA 0.434700 ;
    PORT
      LAYER met2 ;
        RECT 238.370 376.000 238.650 380.000 ;
    END
  END wb_slave_mem_raddr[22]
  PIN wb_slave_mem_raddr[23]
    DIRECTION INPUT ;
    USE SIGNAL ;
    ANTENNAGATEAREA 0.631200 ;
    ANTENNADIFFAREA 0.434700 ;
    PORT
      LAYER met2 ;
        RECT 357.510 376.000 357.790 380.000 ;
    END
  END wb_slave_mem_raddr[23]
  PIN wb_slave_mem_raddr[24]
    DIRECTION INPUT ;
    USE SIGNAL ;
    ANTENNAGATEAREA 0.631200 ;
    ANTENNADIFFAREA 0.434700 ;
    PORT
      LAYER met2 ;
        RECT 228.710 376.000 228.990 380.000 ;
    END
  END wb_slave_mem_raddr[24]
  PIN wb_slave_mem_raddr[25]
    DIRECTION INPUT ;
    USE SIGNAL ;
    ANTENNAGATEAREA 0.631200 ;
    ANTENNADIFFAREA 0.434700 ;
    PORT
      LAYER met2 ;
        RECT 373.610 376.000 373.890 380.000 ;
    END
  END wb_slave_mem_raddr[25]
  PIN wb_slave_mem_raddr[26]
    DIRECTION INPUT ;
    USE SIGNAL ;
    ANTENNAGATEAREA 0.631200 ;
    ANTENNADIFFAREA 0.434700 ;
    PORT
      LAYER met2 ;
        RECT 325.310 376.000 325.590 380.000 ;
    END
  END wb_slave_mem_raddr[26]
  PIN wb_slave_mem_raddr[27]
    DIRECTION INPUT ;
    USE SIGNAL ;
    ANTENNAGATEAREA 0.631200 ;
    ANTENNADIFFAREA 0.434700 ;
    PORT
      LAYER met2 ;
        RECT 347.850 376.000 348.130 380.000 ;
    END
  END wb_slave_mem_raddr[27]
  PIN wb_slave_mem_raddr[28]
    DIRECTION INPUT ;
    USE SIGNAL ;
    PORT
      LAYER met2 ;
        RECT 67.710 0.000 67.990 4.000 ;
    END
  END wb_slave_mem_raddr[28]
  PIN wb_slave_mem_raddr[29]
    DIRECTION INPUT ;
    USE SIGNAL ;
    PORT
      LAYER met2 ;
        RECT 328.530 0.000 328.810 4.000 ;
    END
  END wb_slave_mem_raddr[29]
  PIN wb_slave_mem_raddr[2]
    DIRECTION INPUT ;
    USE SIGNAL ;
    ANTENNAGATEAREA 0.631200 ;
    ANTENNADIFFAREA 0.434700 ;
    PORT
      LAYER met2 ;
        RECT 283.450 376.000 283.730 380.000 ;
    END
  END wb_slave_mem_raddr[2]
  PIN wb_slave_mem_raddr[30]
    DIRECTION INPUT ;
    USE SIGNAL ;
    PORT
      LAYER met2 ;
        RECT 302.770 0.000 303.050 4.000 ;
    END
  END wb_slave_mem_raddr[30]
  PIN wb_slave_mem_raddr[31]
    DIRECTION INPUT ;
    USE SIGNAL ;
    PORT
      LAYER met2 ;
        RECT 83.810 0.000 84.090 4.000 ;
    END
  END wb_slave_mem_raddr[31]
  PIN wb_slave_mem_raddr[3]
    DIRECTION INPUT ;
    USE SIGNAL ;
    ANTENNAGATEAREA 0.631200 ;
    ANTENNADIFFAREA 0.434700 ;
    PORT
      LAYER met2 ;
        RECT 257.690 376.000 257.970 380.000 ;
    END
  END wb_slave_mem_raddr[3]
  PIN wb_slave_mem_raddr[4]
    DIRECTION INPUT ;
    USE SIGNAL ;
    ANTENNAGATEAREA 0.631200 ;
    ANTENNADIFFAREA 0.434700 ;
    PORT
      LAYER met2 ;
        RECT 289.890 376.000 290.170 380.000 ;
    END
  END wb_slave_mem_raddr[4]
  PIN wb_slave_mem_raddr[5]
    DIRECTION INPUT ;
    USE SIGNAL ;
    ANTENNAGATEAREA 0.631200 ;
    ANTENNADIFFAREA 0.434700 ;
    PORT
      LAYER met2 ;
        RECT 293.110 376.000 293.390 380.000 ;
    END
  END wb_slave_mem_raddr[5]
  PIN wb_slave_mem_raddr[6]
    DIRECTION INPUT ;
    USE SIGNAL ;
    ANTENNAGATEAREA 0.631200 ;
    ANTENNADIFFAREA 0.434700 ;
    PORT
      LAYER met2 ;
        RECT 248.030 376.000 248.310 380.000 ;
    END
  END wb_slave_mem_raddr[6]
  PIN wb_slave_mem_raddr[7]
    DIRECTION INPUT ;
    USE SIGNAL ;
    ANTENNAGATEAREA 0.631200 ;
    ANTENNADIFFAREA 0.434700 ;
    PORT
      LAYER met2 ;
        RECT 309.210 376.000 309.490 380.000 ;
    END
  END wb_slave_mem_raddr[7]
  PIN wb_slave_mem_raddr[8]
    DIRECTION INPUT ;
    USE SIGNAL ;
    ANTENNAGATEAREA 0.631200 ;
    ANTENNADIFFAREA 0.434700 ;
    PORT
      LAYER met2 ;
        RECT 328.530 376.000 328.810 380.000 ;
    END
  END wb_slave_mem_raddr[8]
  PIN wb_slave_mem_raddr[9]
    DIRECTION INPUT ;
    USE SIGNAL ;
    ANTENNAGATEAREA 0.631200 ;
    ANTENNADIFFAREA 0.434700 ;
    PORT
      LAYER met2 ;
        RECT 331.750 376.000 332.030 380.000 ;
    END
  END wb_slave_mem_raddr[9]
  PIN wb_slave_mem_rdata[0]
    DIRECTION OUTPUT ;
    USE SIGNAL ;
    ANTENNADIFFAREA 0.340600 ;
    PORT
      LAYER met2 ;
        RECT 296.330 376.000 296.610 380.000 ;
    END
  END wb_slave_mem_rdata[0]
  PIN wb_slave_mem_rdata[10]
    DIRECTION OUTPUT ;
    USE SIGNAL ;
    PORT
      LAYER met2 ;
        RECT 106.350 376.000 106.630 380.000 ;
    END
  END wb_slave_mem_rdata[10]
  PIN wb_slave_mem_rdata[11]
    DIRECTION OUTPUT ;
    USE SIGNAL ;
    PORT
      LAYER met3 ;
        RECT 0.000 292.440 4.000 293.040 ;
    END
  END wb_slave_mem_rdata[11]
  PIN wb_slave_mem_rdata[12]
    DIRECTION OUTPUT ;
    USE SIGNAL ;
    PORT
      LAYER met2 ;
        RECT 302.770 376.000 303.050 380.000 ;
    END
  END wb_slave_mem_rdata[12]
  PIN wb_slave_mem_rdata[13]
    DIRECTION OUTPUT ;
    USE SIGNAL ;
    PORT
      LAYER met2 ;
        RECT 99.910 0.000 100.190 4.000 ;
    END
  END wb_slave_mem_rdata[13]
  PIN wb_slave_mem_rdata[14]
    DIRECTION OUTPUT ;
    USE SIGNAL ;
    PORT
      LAYER met3 ;
        RECT 376.000 74.840 380.000 75.440 ;
    END
  END wb_slave_mem_rdata[14]
  PIN wb_slave_mem_rdata[15]
    DIRECTION OUTPUT ;
    USE SIGNAL ;
    PORT
      LAYER met2 ;
        RECT 132.110 376.000 132.390 380.000 ;
    END
  END wb_slave_mem_rdata[15]
  PIN wb_slave_mem_rdata[16]
    DIRECTION OUTPUT ;
    USE SIGNAL ;
    PORT
      LAYER met3 ;
        RECT 0.000 34.040 4.000 34.640 ;
    END
  END wb_slave_mem_rdata[16]
  PIN wb_slave_mem_rdata[17]
    DIRECTION OUTPUT ;
    USE SIGNAL ;
    PORT
      LAYER met3 ;
        RECT 0.000 272.040 4.000 272.640 ;
    END
  END wb_slave_mem_rdata[17]
  PIN wb_slave_mem_rdata[18]
    DIRECTION OUTPUT ;
    USE SIGNAL ;
    PORT
      LAYER met2 ;
        RECT 354.290 0.000 354.570 4.000 ;
    END
  END wb_slave_mem_rdata[18]
  PIN wb_slave_mem_rdata[19]
    DIRECTION OUTPUT ;
    USE SIGNAL ;
    PORT
      LAYER met3 ;
        RECT 376.000 326.440 380.000 327.040 ;
    END
  END wb_slave_mem_rdata[19]
  PIN wb_slave_mem_rdata[1]
    DIRECTION OUTPUT ;
    USE SIGNAL ;
    PORT
      LAYER met2 ;
        RECT 154.650 0.000 154.930 4.000 ;
    END
  END wb_slave_mem_rdata[1]
  PIN wb_slave_mem_rdata[20]
    DIRECTION OUTPUT ;
    USE SIGNAL ;
    PORT
      LAYER met3 ;
        RECT 0.000 71.440 4.000 72.040 ;
    END
  END wb_slave_mem_rdata[20]
  PIN wb_slave_mem_rdata[21]
    DIRECTION OUTPUT ;
    USE SIGNAL ;
    PORT
      LAYER met3 ;
        RECT 0.000 207.440 4.000 208.040 ;
    END
  END wb_slave_mem_rdata[21]
  PIN wb_slave_mem_rdata[22]
    DIRECTION OUTPUT ;
    USE SIGNAL ;
    PORT
      LAYER met2 ;
        RECT 322.090 376.000 322.370 380.000 ;
    END
  END wb_slave_mem_rdata[22]
  PIN wb_slave_mem_rdata[23]
    DIRECTION OUTPUT ;
    USE SIGNAL ;
    PORT
      LAYER met2 ;
        RECT 96.690 376.000 96.970 380.000 ;
    END
  END wb_slave_mem_rdata[23]
  PIN wb_slave_mem_rdata[24]
    DIRECTION OUTPUT ;
    USE SIGNAL ;
    PORT
      LAYER met3 ;
        RECT 376.000 146.240 380.000 146.840 ;
    END
  END wb_slave_mem_rdata[24]
  PIN wb_slave_mem_rdata[25]
    DIRECTION OUTPUT ;
    USE SIGNAL ;
    PORT
      LAYER met3 ;
        RECT 0.000 173.440 4.000 174.040 ;
    END
  END wb_slave_mem_rdata[25]
  PIN wb_slave_mem_rdata[26]
    DIRECTION OUTPUT ;
    USE SIGNAL ;
    PORT
      LAYER met3 ;
        RECT 0.000 20.440 4.000 21.040 ;
    END
  END wb_slave_mem_rdata[26]
  PIN wb_slave_mem_rdata[27]
    DIRECTION OUTPUT ;
    USE SIGNAL ;
    PORT
      LAYER met3 ;
        RECT 0.000 37.440 4.000 38.040 ;
    END
  END wb_slave_mem_rdata[27]
  PIN wb_slave_mem_rdata[28]
    DIRECTION OUTPUT ;
    USE SIGNAL ;
    PORT
      LAYER met3 ;
        RECT 0.000 224.440 4.000 225.040 ;
    END
  END wb_slave_mem_rdata[28]
  PIN wb_slave_mem_rdata[29]
    DIRECTION OUTPUT ;
    USE SIGNAL ;
    PORT
      LAYER met2 ;
        RECT 51.610 0.000 51.890 4.000 ;
    END
  END wb_slave_mem_rdata[29]
  PIN wb_slave_mem_rdata[2]
    DIRECTION OUTPUT ;
    USE SIGNAL ;
    PORT
      LAYER met3 ;
        RECT 0.000 343.440 4.000 344.040 ;
    END
  END wb_slave_mem_rdata[2]
  PIN wb_slave_mem_rdata[30]
    DIRECTION OUTPUT ;
    USE SIGNAL ;
    PORT
      LAYER met3 ;
        RECT 376.000 357.040 380.000 357.640 ;
    END
  END wb_slave_mem_rdata[30]
  PIN wb_slave_mem_rdata[31]
    DIRECTION OUTPUT ;
    USE SIGNAL ;
    PORT
      LAYER met2 ;
        RECT 35.510 0.000 35.790 4.000 ;
    END
  END wb_slave_mem_rdata[31]
  PIN wb_slave_mem_rdata[3]
    DIRECTION OUTPUT ;
    USE SIGNAL ;
    PORT
      LAYER met3 ;
        RECT 0.000 44.240 4.000 44.840 ;
    END
  END wb_slave_mem_rdata[3]
  PIN wb_slave_mem_rdata[4]
    DIRECTION OUTPUT ;
    USE SIGNAL ;
    PORT
      LAYER met3 ;
        RECT 0.000 312.840 4.000 313.440 ;
    END
  END wb_slave_mem_rdata[4]
  PIN wb_slave_mem_rdata[5]
    DIRECTION OUTPUT ;
    USE SIGNAL ;
    PORT
      LAYER met2 ;
        RECT 128.890 0.000 129.170 4.000 ;
    END
  END wb_slave_mem_rdata[5]
  PIN wb_slave_mem_rdata[6]
    DIRECTION OUTPUT ;
    USE SIGNAL ;
    PORT
      LAYER met2 ;
        RECT 77.370 0.000 77.650 4.000 ;
    END
  END wb_slave_mem_rdata[6]
  PIN wb_slave_mem_rdata[7]
    DIRECTION OUTPUT ;
    USE SIGNAL ;
    PORT
      LAYER met2 ;
        RECT 48.390 376.000 48.670 380.000 ;
    END
  END wb_slave_mem_rdata[7]
  PIN wb_slave_mem_rdata[8]
    DIRECTION OUTPUT ;
    USE SIGNAL ;
    PORT
      LAYER met3 ;
        RECT 0.000 275.440 4.000 276.040 ;
    END
  END wb_slave_mem_rdata[8]
  PIN wb_slave_mem_rdata[9]
    DIRECTION OUTPUT ;
    USE SIGNAL ;
    PORT
      LAYER met2 ;
        RECT 318.870 376.000 319.150 380.000 ;
    END
  END wb_slave_mem_rdata[9]
  PIN wb_slave_mem_rdy
    DIRECTION OUTPUT ;
    USE SIGNAL ;
    ANTENNADIFFAREA 0.340600 ;
    PORT
      LAYER met2 ;
        RECT 264.130 376.000 264.410 380.000 ;
    END
  END wb_slave_mem_rdy
  PIN wb_slave_mem_re
    DIRECTION INPUT ;
    USE SIGNAL ;
    ANTENNAGATEAREA 0.631200 ;
    ANTENNADIFFAREA 0.434700 ;
    PORT
      LAYER met2 ;
        RECT 367.170 376.000 367.450 380.000 ;
    END
  END wb_slave_mem_re
  PIN wb_slave_mem_waddr[0]
    DIRECTION INPUT ;
    USE SIGNAL ;
    ANTENNAGATEAREA 0.647700 ;
    ANTENNADIFFAREA 0.434700 ;
    PORT
      LAYER met3 ;
        RECT 0.000 319.640 4.000 320.240 ;
    END
  END wb_slave_mem_waddr[0]
  PIN wb_slave_mem_waddr[10]
    DIRECTION INPUT ;
    USE SIGNAL ;
    ANTENNAGATEAREA 0.631200 ;
    ANTENNADIFFAREA 0.434700 ;
    PORT
      LAYER met2 ;
        RECT 103.130 376.000 103.410 380.000 ;
    END
  END wb_slave_mem_waddr[10]
  PIN wb_slave_mem_waddr[11]
    DIRECTION INPUT ;
    USE SIGNAL ;
    ANTENNAGATEAREA 0.631200 ;
    ANTENNADIFFAREA 0.434700 ;
    PORT
      LAYER met2 ;
        RECT 154.650 376.000 154.930 380.000 ;
    END
  END wb_slave_mem_waddr[11]
  PIN wb_slave_mem_waddr[12]
    DIRECTION INPUT ;
    USE SIGNAL ;
    ANTENNAGATEAREA 0.631200 ;
    ANTENNADIFFAREA 0.434700 ;
    PORT
      LAYER met2 ;
        RECT 77.370 376.000 77.650 380.000 ;
    END
  END wb_slave_mem_waddr[12]
  PIN wb_slave_mem_waddr[13]
    DIRECTION INPUT ;
    USE SIGNAL ;
    ANTENNAGATEAREA 0.631200 ;
    ANTENNADIFFAREA 0.434700 ;
    PORT
      LAYER met2 ;
        RECT 61.270 376.000 61.550 380.000 ;
    END
  END wb_slave_mem_waddr[13]
  PIN wb_slave_mem_waddr[14]
    DIRECTION INPUT ;
    USE SIGNAL ;
    ANTENNAGATEAREA 0.631200 ;
    ANTENNADIFFAREA 0.434700 ;
    PORT
      LAYER met2 ;
        RECT 19.410 376.000 19.690 380.000 ;
    END
  END wb_slave_mem_waddr[14]
  PIN wb_slave_mem_waddr[15]
    DIRECTION INPUT ;
    USE SIGNAL ;
    ANTENNAGATEAREA 0.631200 ;
    ANTENNADIFFAREA 0.434700 ;
    PORT
      LAYER met2 ;
        RECT 22.630 376.000 22.910 380.000 ;
    END
  END wb_slave_mem_waddr[15]
  PIN wb_slave_mem_waddr[16]
    DIRECTION INPUT ;
    USE SIGNAL ;
    ANTENNAGATEAREA 0.631200 ;
    ANTENNADIFFAREA 0.434700 ;
    PORT
      LAYER met2 ;
        RECT 157.870 376.000 158.150 380.000 ;
    END
  END wb_slave_mem_waddr[16]
  PIN wb_slave_mem_waddr[17]
    DIRECTION INPUT ;
    USE SIGNAL ;
    ANTENNAGATEAREA 0.631200 ;
    ANTENNADIFFAREA 0.434700 ;
    PORT
      LAYER met2 ;
        RECT 144.990 376.000 145.270 380.000 ;
    END
  END wb_slave_mem_waddr[17]
  PIN wb_slave_mem_waddr[18]
    DIRECTION INPUT ;
    USE SIGNAL ;
    ANTENNAGATEAREA 0.631200 ;
    ANTENNADIFFAREA 0.434700 ;
    PORT
      LAYER met2 ;
        RECT 93.470 376.000 93.750 380.000 ;
    END
  END wb_slave_mem_waddr[18]
  PIN wb_slave_mem_waddr[19]
    DIRECTION INPUT ;
    USE SIGNAL ;
    ANTENNAGATEAREA 0.631200 ;
    ANTENNADIFFAREA 0.434700 ;
    PORT
      LAYER met2 ;
        RECT 141.770 376.000 142.050 380.000 ;
    END
  END wb_slave_mem_waddr[19]
  PIN wb_slave_mem_waddr[1]
    DIRECTION INPUT ;
    USE SIGNAL ;
    ANTENNAGATEAREA 0.647700 ;
    ANTENNADIFFAREA 0.434700 ;
    PORT
      LAYER met3 ;
        RECT 0.000 323.040 4.000 323.640 ;
    END
  END wb_slave_mem_waddr[1]
  PIN wb_slave_mem_waddr[20]
    DIRECTION INPUT ;
    USE SIGNAL ;
    ANTENNAGATEAREA 0.631200 ;
    ANTENNADIFFAREA 0.434700 ;
    PORT
      LAYER met2 ;
        RECT 38.730 376.000 39.010 380.000 ;
    END
  END wb_slave_mem_waddr[20]
  PIN wb_slave_mem_waddr[21]
    DIRECTION INPUT ;
    USE SIGNAL ;
    ANTENNAGATEAREA 0.631200 ;
    ANTENNADIFFAREA 0.434700 ;
    PORT
      LAYER met2 ;
        RECT 35.510 376.000 35.790 380.000 ;
    END
  END wb_slave_mem_waddr[21]
  PIN wb_slave_mem_waddr[22]
    DIRECTION INPUT ;
    USE SIGNAL ;
    ANTENNAGATEAREA 0.631200 ;
    ANTENNADIFFAREA 0.434700 ;
    PORT
      LAYER met2 ;
        RECT 138.550 376.000 138.830 380.000 ;
    END
  END wb_slave_mem_waddr[22]
  PIN wb_slave_mem_waddr[23]
    DIRECTION INPUT ;
    USE SIGNAL ;
    ANTENNAGATEAREA 0.631200 ;
    ANTENNADIFFAREA 0.434700 ;
    PORT
      LAYER met2 ;
        RECT 58.050 376.000 58.330 380.000 ;
    END
  END wb_slave_mem_waddr[23]
  PIN wb_slave_mem_waddr[24]
    DIRECTION INPUT ;
    USE SIGNAL ;
    ANTENNAGATEAREA 0.631200 ;
    ANTENNADIFFAREA 0.434700 ;
    PORT
      LAYER met2 ;
        RECT 173.970 376.000 174.250 380.000 ;
    END
  END wb_slave_mem_waddr[24]
  PIN wb_slave_mem_waddr[25]
    DIRECTION INPUT ;
    USE SIGNAL ;
    ANTENNAGATEAREA 0.631200 ;
    ANTENNADIFFAREA 0.434700 ;
    PORT
      LAYER met2 ;
        RECT 177.190 376.000 177.470 380.000 ;
    END
  END wb_slave_mem_waddr[25]
  PIN wb_slave_mem_waddr[26]
    DIRECTION INPUT ;
    USE SIGNAL ;
    ANTENNAGATEAREA 0.631200 ;
    ANTENNADIFFAREA 0.434700 ;
    PORT
      LAYER met2 ;
        RECT 29.070 376.000 29.350 380.000 ;
    END
  END wb_slave_mem_waddr[26]
  PIN wb_slave_mem_waddr[27]
    DIRECTION INPUT ;
    USE SIGNAL ;
    ANTENNAGATEAREA 0.631200 ;
    ANTENNADIFFAREA 0.434700 ;
    PORT
      LAYER met2 ;
        RECT 41.950 376.000 42.230 380.000 ;
    END
  END wb_slave_mem_waddr[27]
  PIN wb_slave_mem_waddr[28]
    DIRECTION INPUT ;
    USE SIGNAL ;
    PORT
      LAYER met2 ;
        RECT 90.250 0.000 90.530 4.000 ;
    END
  END wb_slave_mem_waddr[28]
  PIN wb_slave_mem_waddr[29]
    DIRECTION INPUT ;
    USE SIGNAL ;
    PORT
      LAYER met2 ;
        RECT 334.970 0.000 335.250 4.000 ;
    END
  END wb_slave_mem_waddr[29]
  PIN wb_slave_mem_waddr[2]
    DIRECTION INPUT ;
    USE SIGNAL ;
    ANTENNAGATEAREA 0.631200 ;
    ANTENNADIFFAREA 0.434700 ;
    PORT
      LAYER met3 ;
        RECT 0.000 210.840 4.000 211.440 ;
    END
  END wb_slave_mem_waddr[2]
  PIN wb_slave_mem_waddr[30]
    DIRECTION INPUT ;
    USE SIGNAL ;
    PORT
      LAYER met2 ;
        RECT 296.330 0.000 296.610 4.000 ;
    END
  END wb_slave_mem_waddr[30]
  PIN wb_slave_mem_waddr[31]
    DIRECTION INPUT ;
    USE SIGNAL ;
    PORT
      LAYER met2 ;
        RECT 293.110 0.000 293.390 4.000 ;
    END
  END wb_slave_mem_waddr[31]
  PIN wb_slave_mem_waddr[3]
    DIRECTION INPUT ;
    USE SIGNAL ;
    ANTENNAGATEAREA 0.560700 ;
    ANTENNADIFFAREA 0.434700 ;
    PORT
      LAYER met3 ;
        RECT 0.000 326.440 4.000 327.040 ;
    END
  END wb_slave_mem_waddr[3]
  PIN wb_slave_mem_waddr[4]
    DIRECTION INPUT ;
    USE SIGNAL ;
    ANTENNAGATEAREA 0.631200 ;
    ANTENNADIFFAREA 0.434700 ;
    PORT
      LAYER met3 ;
        RECT 0.000 187.040 4.000 187.640 ;
    END
  END wb_slave_mem_waddr[4]
  PIN wb_slave_mem_waddr[5]
    DIRECTION INPUT ;
    USE SIGNAL ;
    ANTENNAGATEAREA 0.631200 ;
    ANTENNADIFFAREA 0.434700 ;
    PORT
      LAYER met3 ;
        RECT 0.000 190.440 4.000 191.040 ;
    END
  END wb_slave_mem_waddr[5]
  PIN wb_slave_mem_waddr[6]
    DIRECTION INPUT ;
    USE SIGNAL ;
    ANTENNAGATEAREA 0.631200 ;
    ANTENNADIFFAREA 0.434700 ;
    PORT
      LAYER met3 ;
        RECT 0.000 180.240 4.000 180.840 ;
    END
  END wb_slave_mem_waddr[6]
  PIN wb_slave_mem_waddr[7]
    DIRECTION INPUT ;
    USE SIGNAL ;
    ANTENNAGATEAREA 0.631200 ;
    ANTENNADIFFAREA 0.434700 ;
    PORT
      LAYER met3 ;
        RECT 0.000 193.840 4.000 194.440 ;
    END
  END wb_slave_mem_waddr[7]
  PIN wb_slave_mem_waddr[8]
    DIRECTION INPUT ;
    USE SIGNAL ;
    ANTENNAGATEAREA 0.631200 ;
    ANTENNADIFFAREA 0.434700 ;
    PORT
      LAYER met2 ;
        RECT 51.610 376.000 51.890 380.000 ;
    END
  END wb_slave_mem_waddr[8]
  PIN wb_slave_mem_waddr[9]
    DIRECTION INPUT ;
    USE SIGNAL ;
    ANTENNAGATEAREA 0.631200 ;
    ANTENNADIFFAREA 0.434700 ;
    PORT
      LAYER met2 ;
        RECT 151.430 376.000 151.710 380.000 ;
    END
  END wb_slave_mem_waddr[9]
  PIN wb_slave_mem_wdata[0]
    DIRECTION INPUT ;
    USE SIGNAL ;
    ANTENNAGATEAREA 0.647700 ;
    ANTENNADIFFAREA 0.434700 ;
    PORT
      LAYER met2 ;
        RECT 241.590 0.000 241.870 4.000 ;
    END
  END wb_slave_mem_wdata[0]
  PIN wb_slave_mem_wdata[10]
    DIRECTION INPUT ;
    USE SIGNAL ;
    ANTENNAGATEAREA 0.647700 ;
    ANTENNADIFFAREA 0.434700 ;
    PORT
      LAYER met3 ;
        RECT 0.000 142.840 4.000 143.440 ;
    END
  END wb_slave_mem_wdata[10]
  PIN wb_slave_mem_wdata[11]
    DIRECTION INPUT ;
    USE SIGNAL ;
    ANTENNAGATEAREA 0.593700 ;
    ANTENNADIFFAREA 0.434700 ;
    PORT
      LAYER met3 ;
        RECT 0.000 241.440 4.000 242.040 ;
    END
  END wb_slave_mem_wdata[11]
  PIN wb_slave_mem_wdata[12]
    DIRECTION INPUT ;
    USE SIGNAL ;
    ANTENNAGATEAREA 0.647700 ;
    ANTENNADIFFAREA 0.434700 ;
    PORT
      LAYER met2 ;
        RECT 70.930 376.000 71.210 380.000 ;
    END
  END wb_slave_mem_wdata[12]
  PIN wb_slave_mem_wdata[13]
    DIRECTION INPUT ;
    USE SIGNAL ;
    ANTENNAGATEAREA 0.647700 ;
    ANTENNADIFFAREA 0.434700 ;
    PORT
      LAYER met2 ;
        RECT 67.710 376.000 67.990 380.000 ;
    END
  END wb_slave_mem_wdata[13]
  PIN wb_slave_mem_wdata[14]
    DIRECTION INPUT ;
    USE SIGNAL ;
    ANTENNAGATEAREA 0.647700 ;
    ANTENNADIFFAREA 0.434700 ;
    PORT
      LAYER met2 ;
        RECT 80.590 376.000 80.870 380.000 ;
    END
  END wb_slave_mem_wdata[14]
  PIN wb_slave_mem_wdata[15]
    DIRECTION INPUT ;
    USE SIGNAL ;
    ANTENNAGATEAREA 0.631200 ;
    ANTENNADIFFAREA 0.434700 ;
    PORT
      LAYER met3 ;
        RECT 0.000 353.640 4.000 354.240 ;
    END
  END wb_slave_mem_wdata[15]
  PIN wb_slave_mem_wdata[16]
    DIRECTION INPUT ;
    USE SIGNAL ;
    ANTENNAGATEAREA 0.631200 ;
    ANTENNADIFFAREA 0.434700 ;
    PORT
      LAYER met3 ;
        RECT 0.000 231.240 4.000 231.840 ;
    END
  END wb_slave_mem_wdata[16]
  PIN wb_slave_mem_wdata[17]
    DIRECTION INPUT ;
    USE SIGNAL ;
    ANTENNAGATEAREA 0.631200 ;
    ANTENNADIFFAREA 0.434700 ;
    PORT
      LAYER met3 ;
        RECT 0.000 156.440 4.000 157.040 ;
    END
  END wb_slave_mem_wdata[17]
  PIN wb_slave_mem_wdata[18]
    DIRECTION INPUT ;
    USE SIGNAL ;
    ANTENNAGATEAREA 0.631200 ;
    ANTENNADIFFAREA 0.434700 ;
    PORT
      LAYER met3 ;
        RECT 0.000 282.240 4.000 282.840 ;
    END
  END wb_slave_mem_wdata[18]
  PIN wb_slave_mem_wdata[19]
    DIRECTION INPUT ;
    USE SIGNAL ;
    ANTENNAGATEAREA 0.631200 ;
    ANTENNADIFFAREA 0.434700 ;
    PORT
      LAYER met3 ;
        RECT 0.000 125.840 4.000 126.440 ;
    END
  END wb_slave_mem_wdata[19]
  PIN wb_slave_mem_wdata[1]
    DIRECTION INPUT ;
    USE SIGNAL ;
    ANTENNAGATEAREA 0.647700 ;
    ANTENNADIFFAREA 0.434700 ;
    PORT
      LAYER met3 ;
        RECT 376.000 214.240 380.000 214.840 ;
    END
  END wb_slave_mem_wdata[1]
  PIN wb_slave_mem_wdata[20]
    DIRECTION INPUT ;
    USE SIGNAL ;
    ANTENNAGATEAREA 0.647700 ;
    ANTENNADIFFAREA 0.434700 ;
    PORT
      LAYER met3 ;
        RECT 0.000 98.640 4.000 99.240 ;
    END
  END wb_slave_mem_wdata[20]
  PIN wb_slave_mem_wdata[21]
    DIRECTION INPUT ;
    USE SIGNAL ;
    ANTENNAGATEAREA 0.631200 ;
    ANTENNADIFFAREA 0.434700 ;
    PORT
      LAYER met3 ;
        RECT 0.000 78.240 4.000 78.840 ;
    END
  END wb_slave_mem_wdata[21]
  PIN wb_slave_mem_wdata[22]
    DIRECTION INPUT ;
    USE SIGNAL ;
    PORT
      LAYER met2 ;
        RECT 289.890 0.000 290.170 4.000 ;
    END
  END wb_slave_mem_wdata[22]
  PIN wb_slave_mem_wdata[23]
    DIRECTION INPUT ;
    USE SIGNAL ;
    PORT
      LAYER met2 ;
        RECT 96.690 0.000 96.970 4.000 ;
    END
  END wb_slave_mem_wdata[23]
  PIN wb_slave_mem_wdata[24]
    DIRECTION INPUT ;
    USE SIGNAL ;
    PORT
      LAYER met2 ;
        RECT 19.410 0.000 19.690 4.000 ;
    END
  END wb_slave_mem_wdata[24]
  PIN wb_slave_mem_wdata[25]
    DIRECTION INPUT ;
    USE SIGNAL ;
    PORT
      LAYER met2 ;
        RECT 80.590 0.000 80.870 4.000 ;
    END
  END wb_slave_mem_wdata[25]
  PIN wb_slave_mem_wdata[26]
    DIRECTION INPUT ;
    USE SIGNAL ;
    PORT
      LAYER met2 ;
        RECT 325.310 0.000 325.590 4.000 ;
    END
  END wb_slave_mem_wdata[26]
  PIN wb_slave_mem_wdata[27]
    DIRECTION INPUT ;
    USE SIGNAL ;
    PORT
      LAYER met2 ;
        RECT 12.970 0.000 13.250 4.000 ;
    END
  END wb_slave_mem_wdata[27]
  PIN wb_slave_mem_wdata[28]
    DIRECTION INPUT ;
    USE SIGNAL ;
    PORT
      LAYER met2 ;
        RECT 3.310 0.000 3.590 4.000 ;
    END
  END wb_slave_mem_wdata[28]
  PIN wb_slave_mem_wdata[29]
    DIRECTION INPUT ;
    USE SIGNAL ;
    PORT
      LAYER met2 ;
        RECT 74.150 0.000 74.430 4.000 ;
    END
  END wb_slave_mem_wdata[29]
  PIN wb_slave_mem_wdata[2]
    DIRECTION INPUT ;
    USE SIGNAL ;
    ANTENNAGATEAREA 0.647700 ;
    ANTENNADIFFAREA 0.434700 ;
    PORT
      LAYER met2 ;
        RECT 231.930 0.000 232.210 4.000 ;
    END
  END wb_slave_mem_wdata[2]
  PIN wb_slave_mem_wdata[30]
    DIRECTION INPUT ;
    USE SIGNAL ;
    PORT
      LAYER met2 ;
        RECT 22.630 0.000 22.910 4.000 ;
    END
  END wb_slave_mem_wdata[30]
  PIN wb_slave_mem_wdata[31]
    DIRECTION INPUT ;
    USE SIGNAL ;
    PORT
      LAYER met2 ;
        RECT 312.430 0.000 312.710 4.000 ;
    END
  END wb_slave_mem_wdata[31]
  PIN wb_slave_mem_wdata[3]
    DIRECTION INPUT ;
    USE SIGNAL ;
    ANTENNAGATEAREA 0.647700 ;
    ANTENNADIFFAREA 0.434700 ;
    PORT
      LAYER met2 ;
        RECT 235.150 0.000 235.430 4.000 ;
    END
  END wb_slave_mem_wdata[3]
  PIN wb_slave_mem_wdata[4]
    DIRECTION INPUT ;
    USE SIGNAL ;
    ANTENNAGATEAREA 0.647700 ;
    ANTENNADIFFAREA 0.434700 ;
    PORT
      LAYER met2 ;
        RECT 135.330 376.000 135.610 380.000 ;
    END
  END wb_slave_mem_wdata[4]
  PIN wb_slave_mem_wdata[5]
    DIRECTION INPUT ;
    USE SIGNAL ;
    ANTENNAGATEAREA 0.593700 ;
    ANTENNADIFFAREA 0.434700 ;
    PORT
      LAYER met3 ;
        RECT 0.000 221.040 4.000 221.640 ;
    END
  END wb_slave_mem_wdata[5]
  PIN wb_slave_mem_wdata[6]
    DIRECTION INPUT ;
    USE SIGNAL ;
    ANTENNAGATEAREA 0.647700 ;
    ANTENNADIFFAREA 0.434700 ;
    PORT
      LAYER met2 ;
        RECT 161.090 0.000 161.370 4.000 ;
    END
  END wb_slave_mem_wdata[6]
  PIN wb_slave_mem_wdata[7]
    DIRECTION INPUT ;
    USE SIGNAL ;
    ANTENNAGATEAREA 0.647700 ;
    ANTENNADIFFAREA 0.434700 ;
    PORT
      LAYER met3 ;
        RECT 0.000 149.640 4.000 150.240 ;
    END
  END wb_slave_mem_wdata[7]
  PIN wb_slave_mem_wdata[8]
    DIRECTION INPUT ;
    USE SIGNAL ;
    ANTENNAGATEAREA 0.647700 ;
    ANTENNADIFFAREA 0.434700 ;
    PORT
      LAYER met2 ;
        RECT 125.670 0.000 125.950 4.000 ;
    END
  END wb_slave_mem_wdata[8]
  PIN wb_slave_mem_wdata[9]
    DIRECTION INPUT ;
    USE SIGNAL ;
    ANTENNAGATEAREA 0.647700 ;
    ANTENNADIFFAREA 0.434700 ;
    PORT
      LAYER met3 ;
        RECT 376.000 40.840 380.000 41.440 ;
    END
  END wb_slave_mem_wdata[9]
  PIN wb_slave_mem_we
    DIRECTION INPUT ;
    USE SIGNAL ;
    ANTENNAGATEAREA 0.593700 ;
    ANTENNADIFFAREA 0.434700 ;
    PORT
      LAYER met3 ;
        RECT 0.000 183.640 4.000 184.240 ;
    END
  END wb_slave_mem_we
  PIN wb_slave_mem_wmask[0]
    DIRECTION INPUT ;
    USE SIGNAL ;
    PORT
      LAYER met2 ;
        RECT 305.990 0.000 306.270 4.000 ;
    END
  END wb_slave_mem_wmask[0]
  PIN wb_slave_mem_wmask[1]
    DIRECTION INPUT ;
    USE SIGNAL ;
    PORT
      LAYER met2 ;
        RECT 93.470 0.000 93.750 4.000 ;
    END
  END wb_slave_mem_wmask[1]
  PIN wb_slave_mem_wmask[2]
    DIRECTION INPUT ;
    USE SIGNAL ;
    PORT
      LAYER met2 ;
        RECT 70.930 0.000 71.210 4.000 ;
    END
  END wb_slave_mem_wmask[2]
  PIN wb_slave_mem_wmask[3]
    DIRECTION INPUT ;
    USE SIGNAL ;
    PORT
      LAYER met2 ;
        RECT 299.550 0.000 299.830 4.000 ;
    END
  END wb_slave_mem_wmask[3]
  PIN wb_slave_mem_wr_data_ack
    DIRECTION OUTPUT ;
    USE SIGNAL ;
    ANTENNADIFFAREA 0.340600 ;
    PORT
      LAYER met3 ;
        RECT 0.000 176.840 4.000 177.440 ;
    END
  END wb_slave_mem_wr_data_ack
  PIN wb_slave_up_en
    DIRECTION OUTPUT ;
    USE SIGNAL ;
    ANTENNADIFFAREA 0.340600 ;
    PORT
      LAYER met2 ;
        RECT 260.910 376.000 261.190 380.000 ;
    END
  END wb_slave_up_en
  OBS
      LAYER nwell ;
        RECT 5.330 10.760 374.630 367.390 ;
      LAYER li1 ;
        RECT 5.520 10.795 374.440 367.285 ;
      LAYER met1 ;
        RECT 4.210 10.640 377.130 376.680 ;
      LAYER met2 ;
        RECT 4.230 375.720 9.470 376.710 ;
        RECT 10.310 375.720 12.690 376.710 ;
        RECT 13.530 375.720 15.910 376.710 ;
        RECT 16.750 375.720 19.130 376.710 ;
        RECT 19.970 375.720 22.350 376.710 ;
        RECT 23.190 375.720 25.570 376.710 ;
        RECT 26.410 375.720 28.790 376.710 ;
        RECT 29.630 375.720 32.010 376.710 ;
        RECT 32.850 375.720 35.230 376.710 ;
        RECT 36.070 375.720 38.450 376.710 ;
        RECT 39.290 375.720 41.670 376.710 ;
        RECT 42.510 375.720 44.890 376.710 ;
        RECT 45.730 375.720 48.110 376.710 ;
        RECT 48.950 375.720 51.330 376.710 ;
        RECT 52.170 375.720 54.550 376.710 ;
        RECT 55.390 375.720 57.770 376.710 ;
        RECT 58.610 375.720 60.990 376.710 ;
        RECT 61.830 375.720 64.210 376.710 ;
        RECT 65.050 375.720 67.430 376.710 ;
        RECT 68.270 375.720 70.650 376.710 ;
        RECT 71.490 375.720 73.870 376.710 ;
        RECT 74.710 375.720 77.090 376.710 ;
        RECT 77.930 375.720 80.310 376.710 ;
        RECT 81.150 375.720 83.530 376.710 ;
        RECT 84.370 375.720 86.750 376.710 ;
        RECT 87.590 375.720 89.970 376.710 ;
        RECT 90.810 375.720 93.190 376.710 ;
        RECT 94.030 375.720 96.410 376.710 ;
        RECT 97.250 375.720 99.630 376.710 ;
        RECT 100.470 375.720 102.850 376.710 ;
        RECT 103.690 375.720 106.070 376.710 ;
        RECT 106.910 375.720 109.290 376.710 ;
        RECT 110.130 375.720 112.510 376.710 ;
        RECT 113.350 375.720 115.730 376.710 ;
        RECT 116.570 375.720 118.950 376.710 ;
        RECT 119.790 375.720 122.170 376.710 ;
        RECT 123.010 375.720 125.390 376.710 ;
        RECT 126.230 375.720 128.610 376.710 ;
        RECT 129.450 375.720 131.830 376.710 ;
        RECT 132.670 375.720 135.050 376.710 ;
        RECT 135.890 375.720 138.270 376.710 ;
        RECT 139.110 375.720 141.490 376.710 ;
        RECT 142.330 375.720 144.710 376.710 ;
        RECT 145.550 375.720 147.930 376.710 ;
        RECT 148.770 375.720 151.150 376.710 ;
        RECT 151.990 375.720 154.370 376.710 ;
        RECT 155.210 375.720 157.590 376.710 ;
        RECT 158.430 375.720 160.810 376.710 ;
        RECT 161.650 375.720 164.030 376.710 ;
        RECT 164.870 375.720 167.250 376.710 ;
        RECT 168.090 375.720 170.470 376.710 ;
        RECT 171.310 375.720 173.690 376.710 ;
        RECT 174.530 375.720 176.910 376.710 ;
        RECT 177.750 375.720 180.130 376.710 ;
        RECT 180.970 375.720 183.350 376.710 ;
        RECT 184.190 375.720 186.570 376.710 ;
        RECT 187.410 375.720 189.790 376.710 ;
        RECT 190.630 375.720 193.010 376.710 ;
        RECT 193.850 375.720 196.230 376.710 ;
        RECT 197.070 375.720 199.450 376.710 ;
        RECT 200.290 375.720 202.670 376.710 ;
        RECT 203.510 375.720 205.890 376.710 ;
        RECT 206.730 375.720 209.110 376.710 ;
        RECT 209.950 375.720 212.330 376.710 ;
        RECT 213.170 375.720 215.550 376.710 ;
        RECT 216.390 375.720 218.770 376.710 ;
        RECT 219.610 375.720 221.990 376.710 ;
        RECT 222.830 375.720 225.210 376.710 ;
        RECT 226.050 375.720 228.430 376.710 ;
        RECT 229.270 375.720 231.650 376.710 ;
        RECT 232.490 375.720 234.870 376.710 ;
        RECT 235.710 375.720 238.090 376.710 ;
        RECT 238.930 375.720 241.310 376.710 ;
        RECT 242.150 375.720 244.530 376.710 ;
        RECT 245.370 375.720 247.750 376.710 ;
        RECT 248.590 375.720 250.970 376.710 ;
        RECT 251.810 375.720 254.190 376.710 ;
        RECT 255.030 375.720 257.410 376.710 ;
        RECT 258.250 375.720 260.630 376.710 ;
        RECT 261.470 375.720 263.850 376.710 ;
        RECT 264.690 375.720 267.070 376.710 ;
        RECT 267.910 375.720 270.290 376.710 ;
        RECT 271.130 375.720 273.510 376.710 ;
        RECT 274.350 375.720 276.730 376.710 ;
        RECT 277.570 375.720 279.950 376.710 ;
        RECT 280.790 375.720 283.170 376.710 ;
        RECT 284.010 375.720 286.390 376.710 ;
        RECT 287.230 375.720 289.610 376.710 ;
        RECT 290.450 375.720 292.830 376.710 ;
        RECT 293.670 375.720 296.050 376.710 ;
        RECT 296.890 375.720 299.270 376.710 ;
        RECT 300.110 375.720 302.490 376.710 ;
        RECT 303.330 375.720 305.710 376.710 ;
        RECT 306.550 375.720 308.930 376.710 ;
        RECT 309.770 375.720 312.150 376.710 ;
        RECT 312.990 375.720 315.370 376.710 ;
        RECT 316.210 375.720 318.590 376.710 ;
        RECT 319.430 375.720 321.810 376.710 ;
        RECT 322.650 375.720 325.030 376.710 ;
        RECT 325.870 375.720 328.250 376.710 ;
        RECT 329.090 375.720 331.470 376.710 ;
        RECT 332.310 375.720 334.690 376.710 ;
        RECT 335.530 375.720 337.910 376.710 ;
        RECT 338.750 375.720 341.130 376.710 ;
        RECT 341.970 375.720 344.350 376.710 ;
        RECT 345.190 375.720 347.570 376.710 ;
        RECT 348.410 375.720 350.790 376.710 ;
        RECT 351.630 375.720 354.010 376.710 ;
        RECT 354.850 375.720 357.230 376.710 ;
        RECT 358.070 375.720 360.450 376.710 ;
        RECT 361.290 375.720 363.670 376.710 ;
        RECT 364.510 375.720 366.890 376.710 ;
        RECT 367.730 375.720 370.110 376.710 ;
        RECT 370.950 375.720 373.330 376.710 ;
        RECT 374.170 375.720 376.550 376.710 ;
        RECT 4.230 4.280 377.100 375.720 ;
        RECT 4.230 3.670 6.250 4.280 ;
        RECT 7.090 3.670 9.470 4.280 ;
        RECT 10.310 3.670 12.690 4.280 ;
        RECT 13.530 3.670 15.910 4.280 ;
        RECT 16.750 3.670 19.130 4.280 ;
        RECT 19.970 3.670 22.350 4.280 ;
        RECT 23.190 3.670 25.570 4.280 ;
        RECT 26.410 3.670 28.790 4.280 ;
        RECT 29.630 3.670 32.010 4.280 ;
        RECT 32.850 3.670 35.230 4.280 ;
        RECT 36.070 3.670 38.450 4.280 ;
        RECT 39.290 3.670 41.670 4.280 ;
        RECT 42.510 3.670 44.890 4.280 ;
        RECT 45.730 3.670 48.110 4.280 ;
        RECT 48.950 3.670 51.330 4.280 ;
        RECT 52.170 3.670 54.550 4.280 ;
        RECT 55.390 3.670 57.770 4.280 ;
        RECT 58.610 3.670 60.990 4.280 ;
        RECT 61.830 3.670 64.210 4.280 ;
        RECT 65.050 3.670 67.430 4.280 ;
        RECT 68.270 3.670 70.650 4.280 ;
        RECT 71.490 3.670 73.870 4.280 ;
        RECT 74.710 3.670 77.090 4.280 ;
        RECT 77.930 3.670 80.310 4.280 ;
        RECT 81.150 3.670 83.530 4.280 ;
        RECT 84.370 3.670 86.750 4.280 ;
        RECT 87.590 3.670 89.970 4.280 ;
        RECT 90.810 3.670 93.190 4.280 ;
        RECT 94.030 3.670 96.410 4.280 ;
        RECT 97.250 3.670 99.630 4.280 ;
        RECT 100.470 3.670 102.850 4.280 ;
        RECT 103.690 3.670 106.070 4.280 ;
        RECT 106.910 3.670 109.290 4.280 ;
        RECT 110.130 3.670 112.510 4.280 ;
        RECT 113.350 3.670 115.730 4.280 ;
        RECT 116.570 3.670 118.950 4.280 ;
        RECT 119.790 3.670 122.170 4.280 ;
        RECT 123.010 3.670 125.390 4.280 ;
        RECT 126.230 3.670 128.610 4.280 ;
        RECT 129.450 3.670 131.830 4.280 ;
        RECT 132.670 3.670 135.050 4.280 ;
        RECT 135.890 3.670 138.270 4.280 ;
        RECT 139.110 3.670 141.490 4.280 ;
        RECT 142.330 3.670 144.710 4.280 ;
        RECT 145.550 3.670 147.930 4.280 ;
        RECT 148.770 3.670 151.150 4.280 ;
        RECT 151.990 3.670 154.370 4.280 ;
        RECT 155.210 3.670 157.590 4.280 ;
        RECT 158.430 3.670 160.810 4.280 ;
        RECT 161.650 3.670 164.030 4.280 ;
        RECT 164.870 3.670 167.250 4.280 ;
        RECT 168.090 3.670 170.470 4.280 ;
        RECT 171.310 3.670 173.690 4.280 ;
        RECT 174.530 3.670 176.910 4.280 ;
        RECT 177.750 3.670 180.130 4.280 ;
        RECT 180.970 3.670 183.350 4.280 ;
        RECT 184.190 3.670 186.570 4.280 ;
        RECT 187.410 3.670 189.790 4.280 ;
        RECT 190.630 3.670 193.010 4.280 ;
        RECT 193.850 3.670 196.230 4.280 ;
        RECT 197.070 3.670 199.450 4.280 ;
        RECT 200.290 3.670 202.670 4.280 ;
        RECT 203.510 3.670 205.890 4.280 ;
        RECT 206.730 3.670 209.110 4.280 ;
        RECT 209.950 3.670 212.330 4.280 ;
        RECT 213.170 3.670 215.550 4.280 ;
        RECT 216.390 3.670 218.770 4.280 ;
        RECT 219.610 3.670 221.990 4.280 ;
        RECT 222.830 3.670 225.210 4.280 ;
        RECT 226.050 3.670 228.430 4.280 ;
        RECT 229.270 3.670 231.650 4.280 ;
        RECT 232.490 3.670 234.870 4.280 ;
        RECT 235.710 3.670 238.090 4.280 ;
        RECT 238.930 3.670 241.310 4.280 ;
        RECT 242.150 3.670 244.530 4.280 ;
        RECT 245.370 3.670 247.750 4.280 ;
        RECT 248.590 3.670 250.970 4.280 ;
        RECT 251.810 3.670 254.190 4.280 ;
        RECT 255.030 3.670 257.410 4.280 ;
        RECT 258.250 3.670 260.630 4.280 ;
        RECT 261.470 3.670 263.850 4.280 ;
        RECT 264.690 3.670 267.070 4.280 ;
        RECT 267.910 3.670 270.290 4.280 ;
        RECT 271.130 3.670 273.510 4.280 ;
        RECT 274.350 3.670 276.730 4.280 ;
        RECT 277.570 3.670 279.950 4.280 ;
        RECT 280.790 3.670 283.170 4.280 ;
        RECT 284.010 3.670 286.390 4.280 ;
        RECT 287.230 3.670 289.610 4.280 ;
        RECT 290.450 3.670 292.830 4.280 ;
        RECT 293.670 3.670 296.050 4.280 ;
        RECT 296.890 3.670 299.270 4.280 ;
        RECT 300.110 3.670 302.490 4.280 ;
        RECT 303.330 3.670 305.710 4.280 ;
        RECT 306.550 3.670 308.930 4.280 ;
        RECT 309.770 3.670 312.150 4.280 ;
        RECT 312.990 3.670 315.370 4.280 ;
        RECT 316.210 3.670 318.590 4.280 ;
        RECT 319.430 3.670 321.810 4.280 ;
        RECT 322.650 3.670 325.030 4.280 ;
        RECT 325.870 3.670 328.250 4.280 ;
        RECT 329.090 3.670 331.470 4.280 ;
        RECT 332.310 3.670 334.690 4.280 ;
        RECT 335.530 3.670 337.910 4.280 ;
        RECT 338.750 3.670 341.130 4.280 ;
        RECT 341.970 3.670 354.010 4.280 ;
        RECT 354.850 3.670 377.100 4.280 ;
      LAYER met3 ;
        RECT 3.950 364.840 376.010 367.365 ;
        RECT 4.400 363.440 376.010 364.840 ;
        RECT 3.950 361.440 376.010 363.440 ;
        RECT 4.400 360.040 376.010 361.440 ;
        RECT 3.950 358.040 376.010 360.040 ;
        RECT 4.400 356.640 375.600 358.040 ;
        RECT 3.950 354.640 376.010 356.640 ;
        RECT 4.400 353.240 376.010 354.640 ;
        RECT 3.950 351.240 376.010 353.240 ;
        RECT 4.400 349.840 376.010 351.240 ;
        RECT 3.950 347.840 376.010 349.840 ;
        RECT 4.400 346.440 375.600 347.840 ;
        RECT 3.950 344.440 376.010 346.440 ;
        RECT 4.400 343.040 375.600 344.440 ;
        RECT 3.950 341.040 376.010 343.040 ;
        RECT 4.400 339.640 376.010 341.040 ;
        RECT 3.950 337.640 376.010 339.640 ;
        RECT 4.400 336.240 376.010 337.640 ;
        RECT 3.950 334.240 376.010 336.240 ;
        RECT 4.400 332.840 375.600 334.240 ;
        RECT 3.950 330.840 376.010 332.840 ;
        RECT 4.400 329.440 375.600 330.840 ;
        RECT 3.950 327.440 376.010 329.440 ;
        RECT 4.400 326.040 375.600 327.440 ;
        RECT 3.950 324.040 376.010 326.040 ;
        RECT 4.400 322.640 375.600 324.040 ;
        RECT 3.950 320.640 376.010 322.640 ;
        RECT 4.400 319.240 375.600 320.640 ;
        RECT 3.950 317.240 376.010 319.240 ;
        RECT 4.400 315.840 375.600 317.240 ;
        RECT 3.950 313.840 376.010 315.840 ;
        RECT 4.400 312.440 375.600 313.840 ;
        RECT 3.950 310.440 376.010 312.440 ;
        RECT 4.400 309.040 375.600 310.440 ;
        RECT 3.950 307.040 376.010 309.040 ;
        RECT 4.400 305.640 375.600 307.040 ;
        RECT 3.950 303.640 376.010 305.640 ;
        RECT 4.400 302.240 375.600 303.640 ;
        RECT 3.950 300.240 376.010 302.240 ;
        RECT 4.400 298.840 375.600 300.240 ;
        RECT 3.950 296.840 376.010 298.840 ;
        RECT 4.400 295.440 375.600 296.840 ;
        RECT 3.950 293.440 376.010 295.440 ;
        RECT 4.400 292.040 375.600 293.440 ;
        RECT 3.950 290.040 376.010 292.040 ;
        RECT 4.400 288.640 375.600 290.040 ;
        RECT 3.950 286.640 376.010 288.640 ;
        RECT 4.400 285.240 375.600 286.640 ;
        RECT 3.950 283.240 376.010 285.240 ;
        RECT 4.400 281.840 375.600 283.240 ;
        RECT 3.950 279.840 376.010 281.840 ;
        RECT 4.400 278.440 375.600 279.840 ;
        RECT 3.950 276.440 376.010 278.440 ;
        RECT 4.400 275.040 375.600 276.440 ;
        RECT 3.950 273.040 376.010 275.040 ;
        RECT 4.400 271.640 375.600 273.040 ;
        RECT 3.950 269.640 376.010 271.640 ;
        RECT 4.400 268.240 375.600 269.640 ;
        RECT 3.950 266.240 376.010 268.240 ;
        RECT 4.400 264.840 375.600 266.240 ;
        RECT 3.950 262.840 376.010 264.840 ;
        RECT 4.400 261.440 375.600 262.840 ;
        RECT 3.950 259.440 376.010 261.440 ;
        RECT 4.400 258.040 375.600 259.440 ;
        RECT 3.950 256.040 376.010 258.040 ;
        RECT 4.400 254.640 375.600 256.040 ;
        RECT 3.950 252.640 376.010 254.640 ;
        RECT 4.400 251.240 375.600 252.640 ;
        RECT 3.950 249.240 376.010 251.240 ;
        RECT 4.400 247.840 375.600 249.240 ;
        RECT 3.950 245.840 376.010 247.840 ;
        RECT 4.400 244.440 375.600 245.840 ;
        RECT 3.950 242.440 376.010 244.440 ;
        RECT 4.400 241.040 375.600 242.440 ;
        RECT 3.950 239.040 376.010 241.040 ;
        RECT 4.400 237.640 375.600 239.040 ;
        RECT 3.950 235.640 376.010 237.640 ;
        RECT 4.400 234.240 375.600 235.640 ;
        RECT 3.950 232.240 376.010 234.240 ;
        RECT 4.400 230.840 375.600 232.240 ;
        RECT 3.950 228.840 376.010 230.840 ;
        RECT 4.400 227.440 375.600 228.840 ;
        RECT 3.950 225.440 376.010 227.440 ;
        RECT 4.400 224.040 375.600 225.440 ;
        RECT 3.950 222.040 376.010 224.040 ;
        RECT 4.400 220.640 375.600 222.040 ;
        RECT 3.950 218.640 376.010 220.640 ;
        RECT 4.400 217.240 375.600 218.640 ;
        RECT 3.950 215.240 376.010 217.240 ;
        RECT 4.400 213.840 375.600 215.240 ;
        RECT 3.950 211.840 376.010 213.840 ;
        RECT 4.400 210.440 375.600 211.840 ;
        RECT 3.950 208.440 376.010 210.440 ;
        RECT 4.400 207.040 375.600 208.440 ;
        RECT 3.950 205.040 376.010 207.040 ;
        RECT 4.400 203.640 375.600 205.040 ;
        RECT 3.950 201.640 376.010 203.640 ;
        RECT 4.400 200.240 375.600 201.640 ;
        RECT 3.950 198.240 376.010 200.240 ;
        RECT 4.400 196.840 375.600 198.240 ;
        RECT 3.950 194.840 376.010 196.840 ;
        RECT 4.400 193.440 375.600 194.840 ;
        RECT 3.950 191.440 376.010 193.440 ;
        RECT 4.400 190.040 375.600 191.440 ;
        RECT 3.950 188.040 376.010 190.040 ;
        RECT 4.400 186.640 375.600 188.040 ;
        RECT 3.950 184.640 376.010 186.640 ;
        RECT 4.400 183.240 375.600 184.640 ;
        RECT 3.950 181.240 376.010 183.240 ;
        RECT 4.400 179.840 375.600 181.240 ;
        RECT 3.950 177.840 376.010 179.840 ;
        RECT 4.400 176.440 375.600 177.840 ;
        RECT 3.950 174.440 376.010 176.440 ;
        RECT 4.400 173.040 375.600 174.440 ;
        RECT 3.950 171.040 376.010 173.040 ;
        RECT 4.400 169.640 375.600 171.040 ;
        RECT 3.950 167.640 376.010 169.640 ;
        RECT 4.400 166.240 375.600 167.640 ;
        RECT 3.950 164.240 376.010 166.240 ;
        RECT 4.400 162.840 375.600 164.240 ;
        RECT 3.950 160.840 376.010 162.840 ;
        RECT 4.400 159.440 375.600 160.840 ;
        RECT 3.950 157.440 376.010 159.440 ;
        RECT 4.400 156.040 375.600 157.440 ;
        RECT 3.950 154.040 376.010 156.040 ;
        RECT 4.400 152.640 375.600 154.040 ;
        RECT 3.950 150.640 376.010 152.640 ;
        RECT 4.400 149.240 375.600 150.640 ;
        RECT 3.950 147.240 376.010 149.240 ;
        RECT 4.400 145.840 375.600 147.240 ;
        RECT 3.950 143.840 376.010 145.840 ;
        RECT 4.400 142.440 375.600 143.840 ;
        RECT 3.950 140.440 376.010 142.440 ;
        RECT 4.400 139.040 375.600 140.440 ;
        RECT 3.950 137.040 376.010 139.040 ;
        RECT 4.400 135.640 375.600 137.040 ;
        RECT 3.950 133.640 376.010 135.640 ;
        RECT 4.400 132.240 375.600 133.640 ;
        RECT 3.950 130.240 376.010 132.240 ;
        RECT 4.400 128.840 375.600 130.240 ;
        RECT 3.950 126.840 376.010 128.840 ;
        RECT 4.400 125.440 375.600 126.840 ;
        RECT 3.950 123.440 376.010 125.440 ;
        RECT 4.400 122.040 375.600 123.440 ;
        RECT 3.950 120.040 376.010 122.040 ;
        RECT 4.400 118.640 375.600 120.040 ;
        RECT 3.950 116.640 376.010 118.640 ;
        RECT 4.400 115.240 375.600 116.640 ;
        RECT 3.950 113.240 376.010 115.240 ;
        RECT 4.400 111.840 375.600 113.240 ;
        RECT 3.950 109.840 376.010 111.840 ;
        RECT 4.400 108.440 375.600 109.840 ;
        RECT 3.950 106.440 376.010 108.440 ;
        RECT 4.400 105.040 375.600 106.440 ;
        RECT 3.950 103.040 376.010 105.040 ;
        RECT 4.400 101.640 375.600 103.040 ;
        RECT 3.950 99.640 376.010 101.640 ;
        RECT 4.400 98.240 375.600 99.640 ;
        RECT 3.950 96.240 376.010 98.240 ;
        RECT 4.400 94.840 375.600 96.240 ;
        RECT 3.950 92.840 376.010 94.840 ;
        RECT 4.400 91.440 375.600 92.840 ;
        RECT 3.950 89.440 376.010 91.440 ;
        RECT 4.400 88.040 375.600 89.440 ;
        RECT 3.950 86.040 376.010 88.040 ;
        RECT 4.400 84.640 375.600 86.040 ;
        RECT 3.950 82.640 376.010 84.640 ;
        RECT 4.400 81.240 375.600 82.640 ;
        RECT 3.950 79.240 376.010 81.240 ;
        RECT 4.400 77.840 375.600 79.240 ;
        RECT 3.950 75.840 376.010 77.840 ;
        RECT 4.400 74.440 375.600 75.840 ;
        RECT 3.950 72.440 376.010 74.440 ;
        RECT 4.400 71.040 375.600 72.440 ;
        RECT 3.950 69.040 376.010 71.040 ;
        RECT 4.400 67.640 375.600 69.040 ;
        RECT 3.950 65.640 376.010 67.640 ;
        RECT 4.400 64.240 375.600 65.640 ;
        RECT 3.950 62.240 376.010 64.240 ;
        RECT 4.400 60.840 375.600 62.240 ;
        RECT 3.950 58.840 376.010 60.840 ;
        RECT 4.400 57.440 375.600 58.840 ;
        RECT 3.950 55.440 376.010 57.440 ;
        RECT 4.400 54.040 375.600 55.440 ;
        RECT 3.950 52.040 376.010 54.040 ;
        RECT 4.400 50.640 375.600 52.040 ;
        RECT 3.950 48.640 376.010 50.640 ;
        RECT 4.400 47.240 375.600 48.640 ;
        RECT 3.950 45.240 376.010 47.240 ;
        RECT 4.400 43.840 375.600 45.240 ;
        RECT 3.950 41.840 376.010 43.840 ;
        RECT 4.400 40.440 375.600 41.840 ;
        RECT 3.950 38.440 376.010 40.440 ;
        RECT 4.400 37.040 375.600 38.440 ;
        RECT 3.950 35.040 376.010 37.040 ;
        RECT 4.400 33.640 375.600 35.040 ;
        RECT 3.950 31.640 376.010 33.640 ;
        RECT 4.400 30.240 375.600 31.640 ;
        RECT 3.950 28.240 376.010 30.240 ;
        RECT 4.400 26.840 375.600 28.240 ;
        RECT 3.950 21.440 376.010 26.840 ;
        RECT 4.400 20.040 376.010 21.440 ;
        RECT 3.950 10.715 376.010 20.040 ;
      LAYER met4 ;
        RECT 3.975 203.495 20.640 321.465 ;
        RECT 23.040 203.495 23.940 321.465 ;
        RECT 26.340 203.495 174.240 321.465 ;
        RECT 176.640 203.495 177.540 321.465 ;
        RECT 179.940 203.495 327.840 321.465 ;
        RECT 330.240 203.495 331.140 321.465 ;
        RECT 333.540 203.495 375.985 321.465 ;
  END
END command_arbiter_decoder
END LIBRARY

